VERSION 5.7 ;
BUSBITCHARS "[]" ;
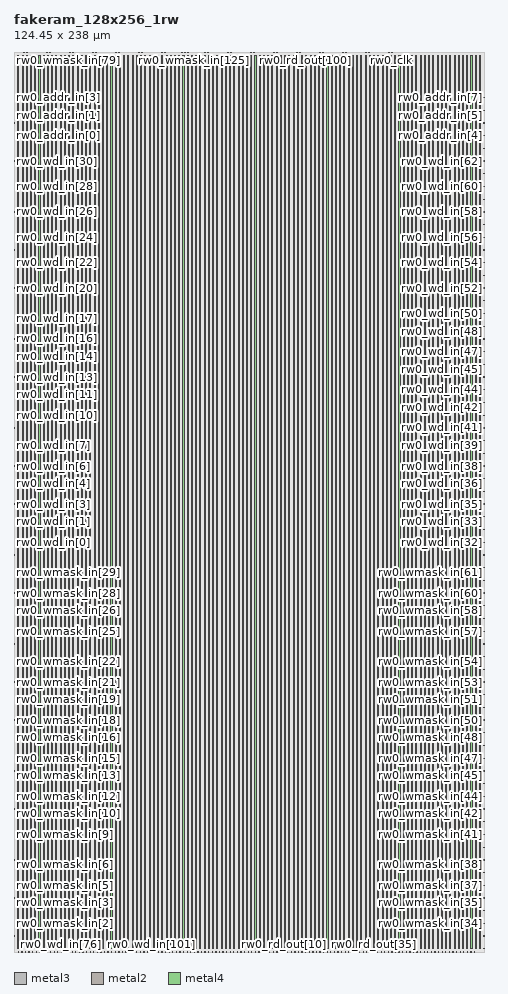
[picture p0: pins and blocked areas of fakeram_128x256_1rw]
MACRO fakeram_128x256_1rw
  FOREIGN fakeram_128x256_1rw 0 0 ;
  SYMMETRY X Y R90 ;
  SIZE 124.450 BY 238.000 ;
  CLASS BLOCK ;
  PIN rw0_wmask_in[0]
    DIRECTION INPUT ;
    USE SIGNAL ;
    SHAPE ABUTMENT ;
    PORT
      LAYER metal3 ;
      RECT 0.000 0.805 0.210 0.875 ;
    END
  END rw0_wmask_in[0]
  PIN rw0_wmask_in[1]
    DIRECTION INPUT ;
    USE SIGNAL ;
    SHAPE ABUTMENT ;
    PORT
      LAYER metal3 ;
      RECT 0.000 4.165 0.210 4.235 ;
    END
  END rw0_wmask_in[1]
  PIN rw0_wmask_in[2]
    DIRECTION INPUT ;
    USE SIGNAL ;
    SHAPE ABUTMENT ;
    PORT
      LAYER metal3 ;
      RECT 0.000 7.525 0.210 7.595 ;
    END
  END rw0_wmask_in[2]
  PIN rw0_wmask_in[3]
    DIRECTION INPUT ;
    USE SIGNAL ;
    SHAPE ABUTMENT ;
    PORT
      LAYER metal3 ;
      RECT 0.000 10.885 0.210 10.955 ;
    END
  END rw0_wmask_in[3]
  PIN rw0_wmask_in[4]
    DIRECTION INPUT ;
    USE SIGNAL ;
    SHAPE ABUTMENT ;
    PORT
      LAYER metal3 ;
      RECT 0.000 14.245 0.210 14.315 ;
    END
  END rw0_wmask_in[4]
  PIN rw0_wmask_in[5]
    DIRECTION INPUT ;
    USE SIGNAL ;
    SHAPE ABUTMENT ;
    PORT
      LAYER metal3 ;
      RECT 0.000 17.605 0.210 17.675 ;
    END
  END rw0_wmask_in[5]
  PIN rw0_wmask_in[6]
    DIRECTION INPUT ;
    USE SIGNAL ;
    SHAPE ABUTMENT ;
    PORT
      LAYER metal3 ;
      RECT 0.000 20.965 0.210 21.035 ;
    END
  END rw0_wmask_in[6]
  PIN rw0_wmask_in[7]
    DIRECTION INPUT ;
    USE SIGNAL ;
    SHAPE ABUTMENT ;
    PORT
      LAYER metal3 ;
      RECT 0.000 24.325 0.210 24.395 ;
    END
  END rw0_wmask_in[7]
  PIN rw0_wmask_in[8]
    DIRECTION INPUT ;
    USE SIGNAL ;
    SHAPE ABUTMENT ;
    PORT
      LAYER metal3 ;
      RECT 0.000 27.685 0.210 27.755 ;
    END
  END rw0_wmask_in[8]
  PIN rw0_wmask_in[9]
    DIRECTION INPUT ;
    USE SIGNAL ;
    SHAPE ABUTMENT ;
    PORT
      LAYER metal3 ;
      RECT 0.000 31.045 0.210 31.115 ;
    END
  END rw0_wmask_in[9]
  PIN rw0_wmask_in[10]
    DIRECTION INPUT ;
    USE SIGNAL ;
    SHAPE ABUTMENT ;
    PORT
      LAYER metal3 ;
      RECT 0.000 34.405 0.210 34.475 ;
    END
  END rw0_wmask_in[10]
  PIN rw0_wmask_in[11]
    DIRECTION INPUT ;
    USE SIGNAL ;
    SHAPE ABUTMENT ;
    PORT
      LAYER metal3 ;
      RECT 0.000 37.765 0.210 37.835 ;
    END
  END rw0_wmask_in[11]
  PIN rw0_wmask_in[12]
    DIRECTION INPUT ;
    USE SIGNAL ;
    SHAPE ABUTMENT ;
    PORT
      LAYER metal3 ;
      RECT 0.000 41.125 0.210 41.195 ;
    END
  END rw0_wmask_in[12]
  PIN rw0_wmask_in[13]
    DIRECTION INPUT ;
    USE SIGNAL ;
    SHAPE ABUTMENT ;
    PORT
      LAYER metal3 ;
      RECT 0.000 44.485 0.210 44.555 ;
    END
  END rw0_wmask_in[13]
  PIN rw0_wmask_in[14]
    DIRECTION INPUT ;
    USE SIGNAL ;
    SHAPE ABUTMENT ;
    PORT
      LAYER metal3 ;
      RECT 0.000 47.845 0.210 47.915 ;
    END
  END rw0_wmask_in[14]
  PIN rw0_wmask_in[15]
    DIRECTION INPUT ;
    USE SIGNAL ;
    SHAPE ABUTMENT ;
    PORT
      LAYER metal3 ;
      RECT 0.000 51.205 0.210 51.275 ;
    END
  END rw0_wmask_in[15]
  PIN rw0_wmask_in[16]
    DIRECTION INPUT ;
    USE SIGNAL ;
    SHAPE ABUTMENT ;
    PORT
      LAYER metal3 ;
      RECT 0.000 54.565 0.210 54.635 ;
    END
  END rw0_wmask_in[16]
  PIN rw0_wmask_in[17]
    DIRECTION INPUT ;
    USE SIGNAL ;
    SHAPE ABUTMENT ;
    PORT
      LAYER metal3 ;
      RECT 0.000 57.925 0.210 57.995 ;
    END
  END rw0_wmask_in[17]
  PIN rw0_wmask_in[18]
    DIRECTION INPUT ;
    USE SIGNAL ;
    SHAPE ABUTMENT ;
    PORT
      LAYER metal3 ;
      RECT 0.000 61.285 0.210 61.355 ;
    END
  END rw0_wmask_in[18]
  PIN rw0_wmask_in[19]
    DIRECTION INPUT ;
    USE SIGNAL ;
    SHAPE ABUTMENT ;
    PORT
      LAYER metal3 ;
      RECT 0.000 64.645 0.210 64.715 ;
    END
  END rw0_wmask_in[19]
  PIN rw0_wmask_in[20]
    DIRECTION INPUT ;
    USE SIGNAL ;
    SHAPE ABUTMENT ;
    PORT
      LAYER metal3 ;
      RECT 0.000 68.005 0.210 68.075 ;
    END
  END rw0_wmask_in[20]
  PIN rw0_wmask_in[21]
    DIRECTION INPUT ;
    USE SIGNAL ;
    SHAPE ABUTMENT ;
    PORT
      LAYER metal3 ;
      RECT 0.000 71.365 0.210 71.435 ;
    END
  END rw0_wmask_in[21]
  PIN rw0_wmask_in[22]
    DIRECTION INPUT ;
    USE SIGNAL ;
    SHAPE ABUTMENT ;
    PORT
      LAYER metal3 ;
      RECT 0.000 74.725 0.210 74.795 ;
    END
  END rw0_wmask_in[22]
  PIN rw0_wmask_in[23]
    DIRECTION INPUT ;
    USE SIGNAL ;
    SHAPE ABUTMENT ;
    PORT
      LAYER metal3 ;
      RECT 0.000 78.085 0.210 78.155 ;
    END
  END rw0_wmask_in[23]
  PIN rw0_wmask_in[24]
    DIRECTION INPUT ;
    USE SIGNAL ;
    SHAPE ABUTMENT ;
    PORT
      LAYER metal3 ;
      RECT 0.000 81.445 0.210 81.515 ;
    END
  END rw0_wmask_in[24]
  PIN rw0_wmask_in[25]
    DIRECTION INPUT ;
    USE SIGNAL ;
    SHAPE ABUTMENT ;
    PORT
      LAYER metal3 ;
      RECT 0.000 84.805 0.210 84.875 ;
    END
  END rw0_wmask_in[25]
  PIN rw0_wmask_in[26]
    DIRECTION INPUT ;
    USE SIGNAL ;
    SHAPE ABUTMENT ;
    PORT
      LAYER metal3 ;
      RECT 0.000 88.165 0.210 88.235 ;
    END
  END rw0_wmask_in[26]
  PIN rw0_wmask_in[27]
    DIRECTION INPUT ;
    USE SIGNAL ;
    SHAPE ABUTMENT ;
    PORT
      LAYER metal3 ;
      RECT 0.000 91.525 0.210 91.595 ;
    END
  END rw0_wmask_in[27]
  PIN rw0_wmask_in[28]
    DIRECTION INPUT ;
    USE SIGNAL ;
    SHAPE ABUTMENT ;
    PORT
      LAYER metal3 ;
      RECT 0.000 94.885 0.210 94.955 ;
    END
  END rw0_wmask_in[28]
  PIN rw0_wmask_in[29]
    DIRECTION INPUT ;
    USE SIGNAL ;
    SHAPE ABUTMENT ;
    PORT
      LAYER metal3 ;
      RECT 0.000 98.245 0.210 98.315 ;
    END
  END rw0_wmask_in[29]
  PIN rw0_wmask_in[30]
    DIRECTION INPUT ;
    USE SIGNAL ;
    SHAPE ABUTMENT ;
    PORT
      LAYER metal3 ;
      RECT 0.000 101.605 0.210 101.675 ;
    END
  END rw0_wmask_in[30]
  PIN rw0_wmask_in[31]
    DIRECTION INPUT ;
    USE SIGNAL ;
    SHAPE ABUTMENT ;
    PORT
      LAYER metal3 ;
      RECT 0.000 104.965 0.210 105.035 ;
    END
  END rw0_wmask_in[31]
  PIN rw0_wmask_in[32]
    DIRECTION INPUT ;
    USE SIGNAL ;
    SHAPE ABUTMENT ;
    PORT
      LAYER metal3 ;
      RECT 124.240 0.805 124.450 0.875 ;
    END
  END rw0_wmask_in[32]
  PIN rw0_wmask_in[33]
    DIRECTION INPUT ;
    USE SIGNAL ;
    SHAPE ABUTMENT ;
    PORT
      LAYER metal3 ;
      RECT 124.240 4.165 124.450 4.235 ;
    END
  END rw0_wmask_in[33]
  PIN rw0_wmask_in[34]
    DIRECTION INPUT ;
    USE SIGNAL ;
    SHAPE ABUTMENT ;
    PORT
      LAYER metal3 ;
      RECT 124.240 7.525 124.450 7.595 ;
    END
  END rw0_wmask_in[34]
  PIN rw0_wmask_in[35]
    DIRECTION INPUT ;
    USE SIGNAL ;
    SHAPE ABUTMENT ;
    PORT
      LAYER metal3 ;
      RECT 124.240 10.885 124.450 10.955 ;
    END
  END rw0_wmask_in[35]
  PIN rw0_wmask_in[36]
    DIRECTION INPUT ;
    USE SIGNAL ;
    SHAPE ABUTMENT ;
    PORT
      LAYER metal3 ;
      RECT 124.240 14.245 124.450 14.315 ;
    END
  END rw0_wmask_in[36]
  PIN rw0_wmask_in[37]
    DIRECTION INPUT ;
    USE SIGNAL ;
    SHAPE ABUTMENT ;
    PORT
      LAYER metal3 ;
      RECT 124.240 17.605 124.450 17.675 ;
    END
  END rw0_wmask_in[37]
  PIN rw0_wmask_in[38]
    DIRECTION INPUT ;
    USE SIGNAL ;
    SHAPE ABUTMENT ;
    PORT
      LAYER metal3 ;
      RECT 124.240 20.965 124.450 21.035 ;
    END
  END rw0_wmask_in[38]
  PIN rw0_wmask_in[39]
    DIRECTION INPUT ;
    USE SIGNAL ;
    SHAPE ABUTMENT ;
    PORT
      LAYER metal3 ;
      RECT 124.240 24.325 124.450 24.395 ;
    END
  END rw0_wmask_in[39]
  PIN rw0_wmask_in[40]
    DIRECTION INPUT ;
    USE SIGNAL ;
    SHAPE ABUTMENT ;
    PORT
      LAYER metal3 ;
      RECT 124.240 27.685 124.450 27.755 ;
    END
  END rw0_wmask_in[40]
  PIN rw0_wmask_in[41]
    DIRECTION INPUT ;
    USE SIGNAL ;
    SHAPE ABUTMENT ;
    PORT
      LAYER metal3 ;
      RECT 124.240 31.045 124.450 31.115 ;
    END
  END rw0_wmask_in[41]
  PIN rw0_wmask_in[42]
    DIRECTION INPUT ;
    USE SIGNAL ;
    SHAPE ABUTMENT ;
    PORT
      LAYER metal3 ;
      RECT 124.240 34.405 124.450 34.475 ;
    END
  END rw0_wmask_in[42]
  PIN rw0_wmask_in[43]
    DIRECTION INPUT ;
    USE SIGNAL ;
    SHAPE ABUTMENT ;
    PORT
      LAYER metal3 ;
      RECT 124.240 37.765 124.450 37.835 ;
    END
  END rw0_wmask_in[43]
  PIN rw0_wmask_in[44]
    DIRECTION INPUT ;
    USE SIGNAL ;
    SHAPE ABUTMENT ;
    PORT
      LAYER metal3 ;
      RECT 124.240 41.125 124.450 41.195 ;
    END
  END rw0_wmask_in[44]
  PIN rw0_wmask_in[45]
    DIRECTION INPUT ;
    USE SIGNAL ;
    SHAPE ABUTMENT ;
    PORT
      LAYER metal3 ;
      RECT 124.240 44.485 124.450 44.555 ;
    END
  END rw0_wmask_in[45]
  PIN rw0_wmask_in[46]
    DIRECTION INPUT ;
    USE SIGNAL ;
    SHAPE ABUTMENT ;
    PORT
      LAYER metal3 ;
      RECT 124.240 47.845 124.450 47.915 ;
    END
  END rw0_wmask_in[46]
  PIN rw0_wmask_in[47]
    DIRECTION INPUT ;
    USE SIGNAL ;
    SHAPE ABUTMENT ;
    PORT
      LAYER metal3 ;
      RECT 124.240 51.205 124.450 51.275 ;
    END
  END rw0_wmask_in[47]
  PIN rw0_wmask_in[48]
    DIRECTION INPUT ;
    USE SIGNAL ;
    SHAPE ABUTMENT ;
    PORT
      LAYER metal3 ;
      RECT 124.240 54.565 124.450 54.635 ;
    END
  END rw0_wmask_in[48]
  PIN rw0_wmask_in[49]
    DIRECTION INPUT ;
    USE SIGNAL ;
    SHAPE ABUTMENT ;
    PORT
      LAYER metal3 ;
      RECT 124.240 57.925 124.450 57.995 ;
    END
  END rw0_wmask_in[49]
  PIN rw0_wmask_in[50]
    DIRECTION INPUT ;
    USE SIGNAL ;
    SHAPE ABUTMENT ;
    PORT
      LAYER metal3 ;
      RECT 124.240 61.285 124.450 61.355 ;
    END
  END rw0_wmask_in[50]
  PIN rw0_wmask_in[51]
    DIRECTION INPUT ;
    USE SIGNAL ;
    SHAPE ABUTMENT ;
    PORT
      LAYER metal3 ;
      RECT 124.240 64.645 124.450 64.715 ;
    END
  END rw0_wmask_in[51]
  PIN rw0_wmask_in[52]
    DIRECTION INPUT ;
    USE SIGNAL ;
    SHAPE ABUTMENT ;
    PORT
      LAYER metal3 ;
      RECT 124.240 68.005 124.450 68.075 ;
    END
  END rw0_wmask_in[52]
  PIN rw0_wmask_in[53]
    DIRECTION INPUT ;
    USE SIGNAL ;
    SHAPE ABUTMENT ;
    PORT
      LAYER metal3 ;
      RECT 124.240 71.365 124.450 71.435 ;
    END
  END rw0_wmask_in[53]
  PIN rw0_wmask_in[54]
    DIRECTION INPUT ;
    USE SIGNAL ;
    SHAPE ABUTMENT ;
    PORT
      LAYER metal3 ;
      RECT 124.240 74.725 124.450 74.795 ;
    END
  END rw0_wmask_in[54]
  PIN rw0_wmask_in[55]
    DIRECTION INPUT ;
    USE SIGNAL ;
    SHAPE ABUTMENT ;
    PORT
      LAYER metal3 ;
      RECT 124.240 78.085 124.450 78.155 ;
    END
  END rw0_wmask_in[55]
  PIN rw0_wmask_in[56]
    DIRECTION INPUT ;
    USE SIGNAL ;
    SHAPE ABUTMENT ;
    PORT
      LAYER metal3 ;
      RECT 124.240 81.445 124.450 81.515 ;
    END
  END rw0_wmask_in[56]
  PIN rw0_wmask_in[57]
    DIRECTION INPUT ;
    USE SIGNAL ;
    SHAPE ABUTMENT ;
    PORT
      LAYER metal3 ;
      RECT 124.240 84.805 124.450 84.875 ;
    END
  END rw0_wmask_in[57]
  PIN rw0_wmask_in[58]
    DIRECTION INPUT ;
    USE SIGNAL ;
    SHAPE ABUTMENT ;
    PORT
      LAYER metal3 ;
      RECT 124.240 88.165 124.450 88.235 ;
    END
  END rw0_wmask_in[58]
  PIN rw0_wmask_in[59]
    DIRECTION INPUT ;
    USE SIGNAL ;
    SHAPE ABUTMENT ;
    PORT
      LAYER metal3 ;
      RECT 124.240 91.525 124.450 91.595 ;
    END
  END rw0_wmask_in[59]
  PIN rw0_wmask_in[60]
    DIRECTION INPUT ;
    USE SIGNAL ;
    SHAPE ABUTMENT ;
    PORT
      LAYER metal3 ;
      RECT 124.240 94.885 124.450 94.955 ;
    END
  END rw0_wmask_in[60]
  PIN rw0_wmask_in[61]
    DIRECTION INPUT ;
    USE SIGNAL ;
    SHAPE ABUTMENT ;
    PORT
      LAYER metal3 ;
      RECT 124.240 98.245 124.450 98.315 ;
    END
  END rw0_wmask_in[61]
  PIN rw0_wmask_in[62]
    DIRECTION INPUT ;
    USE SIGNAL ;
    SHAPE ABUTMENT ;
    PORT
      LAYER metal3 ;
      RECT 124.240 101.605 124.450 101.675 ;
    END
  END rw0_wmask_in[62]
  PIN rw0_wmask_in[63]
    DIRECTION INPUT ;
    USE SIGNAL ;
    SHAPE ABUTMENT ;
    PORT
      LAYER metal3 ;
      RECT 124.240 104.965 124.450 105.035 ;
    END
  END rw0_wmask_in[63]
  PIN rw0_wmask_in[64]
    DIRECTION INPUT ;
    USE SIGNAL ;
    SHAPE ABUTMENT ;
    PORT
      LAYER metal2 ;
      RECT 1.105 237.790 1.175 238.000 ;
    END
  END rw0_wmask_in[64]
  PIN rw0_wmask_in[65]
    DIRECTION INPUT ;
    USE SIGNAL ;
    SHAPE ABUTMENT ;
    PORT
      LAYER metal2 ;
      RECT 1.865 237.790 1.935 238.000 ;
    END
  END rw0_wmask_in[65]
  PIN rw0_wmask_in[66]
    DIRECTION INPUT ;
    USE SIGNAL ;
    SHAPE ABUTMENT ;
    PORT
      LAYER metal2 ;
      RECT 2.625 237.790 2.695 238.000 ;
    END
  END rw0_wmask_in[66]
  PIN rw0_wmask_in[67]
    DIRECTION INPUT ;
    USE SIGNAL ;
    SHAPE ABUTMENT ;
    PORT
      LAYER metal2 ;
      RECT 3.385 237.790 3.455 238.000 ;
    END
  END rw0_wmask_in[67]
  PIN rw0_wmask_in[68]
    DIRECTION INPUT ;
    USE SIGNAL ;
    SHAPE ABUTMENT ;
    PORT
      LAYER metal2 ;
      RECT 4.145 237.790 4.215 238.000 ;
    END
  END rw0_wmask_in[68]
  PIN rw0_wmask_in[69]
    DIRECTION INPUT ;
    USE SIGNAL ;
    SHAPE ABUTMENT ;
    PORT
      LAYER metal2 ;
      RECT 4.905 237.790 4.975 238.000 ;
    END
  END rw0_wmask_in[69]
  PIN rw0_wmask_in[70]
    DIRECTION INPUT ;
    USE SIGNAL ;
    SHAPE ABUTMENT ;
    PORT
      LAYER metal2 ;
      RECT 5.665 237.790 5.735 238.000 ;
    END
  END rw0_wmask_in[70]
  PIN rw0_wmask_in[71]
    DIRECTION INPUT ;
    USE SIGNAL ;
    SHAPE ABUTMENT ;
    PORT
      LAYER metal2 ;
      RECT 6.425 237.790 6.495 238.000 ;
    END
  END rw0_wmask_in[71]
  PIN rw0_wmask_in[72]
    DIRECTION INPUT ;
    USE SIGNAL ;
    SHAPE ABUTMENT ;
    PORT
      LAYER metal2 ;
      RECT 7.185 237.790 7.255 238.000 ;
    END
  END rw0_wmask_in[72]
  PIN rw0_wmask_in[73]
    DIRECTION INPUT ;
    USE SIGNAL ;
    SHAPE ABUTMENT ;
    PORT
      LAYER metal2 ;
      RECT 7.945 237.790 8.015 238.000 ;
    END
  END rw0_wmask_in[73]
  PIN rw0_wmask_in[74]
    DIRECTION INPUT ;
    USE SIGNAL ;
    SHAPE ABUTMENT ;
    PORT
      LAYER metal2 ;
      RECT 8.705 237.790 8.775 238.000 ;
    END
  END rw0_wmask_in[74]
  PIN rw0_wmask_in[75]
    DIRECTION INPUT ;
    USE SIGNAL ;
    SHAPE ABUTMENT ;
    PORT
      LAYER metal2 ;
      RECT 9.465 237.790 9.535 238.000 ;
    END
  END rw0_wmask_in[75]
  PIN rw0_wmask_in[76]
    DIRECTION INPUT ;
    USE SIGNAL ;
    SHAPE ABUTMENT ;
    PORT
      LAYER metal2 ;
      RECT 10.225 237.790 10.295 238.000 ;
    END
  END rw0_wmask_in[76]
  PIN rw0_wmask_in[77]
    DIRECTION INPUT ;
    USE SIGNAL ;
    SHAPE ABUTMENT ;
    PORT
      LAYER metal2 ;
      RECT 10.985 237.790 11.055 238.000 ;
    END
  END rw0_wmask_in[77]
  PIN rw0_wmask_in[78]
    DIRECTION INPUT ;
    USE SIGNAL ;
    SHAPE ABUTMENT ;
    PORT
      LAYER metal2 ;
      RECT 11.745 237.790 11.815 238.000 ;
    END
  END rw0_wmask_in[78]
  PIN rw0_wmask_in[79]
    DIRECTION INPUT ;
    USE SIGNAL ;
    SHAPE ABUTMENT ;
    PORT
      LAYER metal2 ;
      RECT 12.505 237.790 12.575 238.000 ;
    END
  END rw0_wmask_in[79]
  PIN rw0_wmask_in[80]
    DIRECTION INPUT ;
    USE SIGNAL ;
    SHAPE ABUTMENT ;
    PORT
      LAYER metal2 ;
      RECT 13.265 237.790 13.335 238.000 ;
    END
  END rw0_wmask_in[80]
  PIN rw0_wmask_in[81]
    DIRECTION INPUT ;
    USE SIGNAL ;
    SHAPE ABUTMENT ;
    PORT
      LAYER metal2 ;
      RECT 14.025 237.790 14.095 238.000 ;
    END
  END rw0_wmask_in[81]
  PIN rw0_wmask_in[82]
    DIRECTION INPUT ;
    USE SIGNAL ;
    SHAPE ABUTMENT ;
    PORT
      LAYER metal2 ;
      RECT 14.785 237.790 14.855 238.000 ;
    END
  END rw0_wmask_in[82]
  PIN rw0_wmask_in[83]
    DIRECTION INPUT ;
    USE SIGNAL ;
    SHAPE ABUTMENT ;
    PORT
      LAYER metal2 ;
      RECT 15.545 237.790 15.615 238.000 ;
    END
  END rw0_wmask_in[83]
  PIN rw0_wmask_in[84]
    DIRECTION INPUT ;
    USE SIGNAL ;
    SHAPE ABUTMENT ;
    PORT
      LAYER metal2 ;
      RECT 16.305 237.790 16.375 238.000 ;
    END
  END rw0_wmask_in[84]
  PIN rw0_wmask_in[85]
    DIRECTION INPUT ;
    USE SIGNAL ;
    SHAPE ABUTMENT ;
    PORT
      LAYER metal2 ;
      RECT 17.065 237.790 17.135 238.000 ;
    END
  END rw0_wmask_in[85]
  PIN rw0_wmask_in[86]
    DIRECTION INPUT ;
    USE SIGNAL ;
    SHAPE ABUTMENT ;
    PORT
      LAYER metal2 ;
      RECT 17.825 237.790 17.895 238.000 ;
    END
  END rw0_wmask_in[86]
  PIN rw0_wmask_in[87]
    DIRECTION INPUT ;
    USE SIGNAL ;
    SHAPE ABUTMENT ;
    PORT
      LAYER metal2 ;
      RECT 18.585 237.790 18.655 238.000 ;
    END
  END rw0_wmask_in[87]
  PIN rw0_wmask_in[88]
    DIRECTION INPUT ;
    USE SIGNAL ;
    SHAPE ABUTMENT ;
    PORT
      LAYER metal2 ;
      RECT 19.345 237.790 19.415 238.000 ;
    END
  END rw0_wmask_in[88]
  PIN rw0_wmask_in[89]
    DIRECTION INPUT ;
    USE SIGNAL ;
    SHAPE ABUTMENT ;
    PORT
      LAYER metal2 ;
      RECT 20.105 237.790 20.175 238.000 ;
    END
  END rw0_wmask_in[89]
  PIN rw0_wmask_in[90]
    DIRECTION INPUT ;
    USE SIGNAL ;
    SHAPE ABUTMENT ;
    PORT
      LAYER metal2 ;
      RECT 20.865 237.790 20.935 238.000 ;
    END
  END rw0_wmask_in[90]
  PIN rw0_wmask_in[91]
    DIRECTION INPUT ;
    USE SIGNAL ;
    SHAPE ABUTMENT ;
    PORT
      LAYER metal2 ;
      RECT 21.625 237.790 21.695 238.000 ;
    END
  END rw0_wmask_in[91]
  PIN rw0_wmask_in[92]
    DIRECTION INPUT ;
    USE SIGNAL ;
    SHAPE ABUTMENT ;
    PORT
      LAYER metal2 ;
      RECT 22.385 237.790 22.455 238.000 ;
    END
  END rw0_wmask_in[92]
  PIN rw0_wmask_in[93]
    DIRECTION INPUT ;
    USE SIGNAL ;
    SHAPE ABUTMENT ;
    PORT
      LAYER metal2 ;
      RECT 23.145 237.790 23.215 238.000 ;
    END
  END rw0_wmask_in[93]
  PIN rw0_wmask_in[94]
    DIRECTION INPUT ;
    USE SIGNAL ;
    SHAPE ABUTMENT ;
    PORT
      LAYER metal2 ;
      RECT 23.905 237.790 23.975 238.000 ;
    END
  END rw0_wmask_in[94]
  PIN rw0_wmask_in[95]
    DIRECTION INPUT ;
    USE SIGNAL ;
    SHAPE ABUTMENT ;
    PORT
      LAYER metal2 ;
      RECT 24.665 237.790 24.735 238.000 ;
    END
  END rw0_wmask_in[95]
  PIN rw0_wmask_in[96]
    DIRECTION INPUT ;
    USE SIGNAL ;
    SHAPE ABUTMENT ;
    PORT
      LAYER metal2 ;
      RECT 25.425 237.790 25.495 238.000 ;
    END
  END rw0_wmask_in[96]
  PIN rw0_wmask_in[97]
    DIRECTION INPUT ;
    USE SIGNAL ;
    SHAPE ABUTMENT ;
    PORT
      LAYER metal2 ;
      RECT 26.185 237.790 26.255 238.000 ;
    END
  END rw0_wmask_in[97]
  PIN rw0_wmask_in[98]
    DIRECTION INPUT ;
    USE SIGNAL ;
    SHAPE ABUTMENT ;
    PORT
      LAYER metal2 ;
      RECT 26.945 237.790 27.015 238.000 ;
    END
  END rw0_wmask_in[98]
  PIN rw0_wmask_in[99]
    DIRECTION INPUT ;
    USE SIGNAL ;
    SHAPE ABUTMENT ;
    PORT
      LAYER metal2 ;
      RECT 27.705 237.790 27.775 238.000 ;
    END
  END rw0_wmask_in[99]
  PIN rw0_wmask_in[100]
    DIRECTION INPUT ;
    USE SIGNAL ;
    SHAPE ABUTMENT ;
    PORT
      LAYER metal2 ;
      RECT 28.465 237.790 28.535 238.000 ;
    END
  END rw0_wmask_in[100]
  PIN rw0_wmask_in[101]
    DIRECTION INPUT ;
    USE SIGNAL ;
    SHAPE ABUTMENT ;
    PORT
      LAYER metal2 ;
      RECT 29.225 237.790 29.295 238.000 ;
    END
  END rw0_wmask_in[101]
  PIN rw0_wmask_in[102]
    DIRECTION INPUT ;
    USE SIGNAL ;
    SHAPE ABUTMENT ;
    PORT
      LAYER metal2 ;
      RECT 29.985 237.790 30.055 238.000 ;
    END
  END rw0_wmask_in[102]
  PIN rw0_wmask_in[103]
    DIRECTION INPUT ;
    USE SIGNAL ;
    SHAPE ABUTMENT ;
    PORT
      LAYER metal2 ;
      RECT 30.745 237.790 30.815 238.000 ;
    END
  END rw0_wmask_in[103]
  PIN rw0_wmask_in[104]
    DIRECTION INPUT ;
    USE SIGNAL ;
    SHAPE ABUTMENT ;
    PORT
      LAYER metal2 ;
      RECT 31.505 237.790 31.575 238.000 ;
    END
  END rw0_wmask_in[104]
  PIN rw0_wmask_in[105]
    DIRECTION INPUT ;
    USE SIGNAL ;
    SHAPE ABUTMENT ;
    PORT
      LAYER metal2 ;
      RECT 32.265 237.790 32.335 238.000 ;
    END
  END rw0_wmask_in[105]
  PIN rw0_wmask_in[106]
    DIRECTION INPUT ;
    USE SIGNAL ;
    SHAPE ABUTMENT ;
    PORT
      LAYER metal2 ;
      RECT 33.025 237.790 33.095 238.000 ;
    END
  END rw0_wmask_in[106]
  PIN rw0_wmask_in[107]
    DIRECTION INPUT ;
    USE SIGNAL ;
    SHAPE ABUTMENT ;
    PORT
      LAYER metal2 ;
      RECT 33.785 237.790 33.855 238.000 ;
    END
  END rw0_wmask_in[107]
  PIN rw0_wmask_in[108]
    DIRECTION INPUT ;
    USE SIGNAL ;
    SHAPE ABUTMENT ;
    PORT
      LAYER metal2 ;
      RECT 34.545 237.790 34.615 238.000 ;
    END
  END rw0_wmask_in[108]
  PIN rw0_wmask_in[109]
    DIRECTION INPUT ;
    USE SIGNAL ;
    SHAPE ABUTMENT ;
    PORT
      LAYER metal2 ;
      RECT 35.305 237.790 35.375 238.000 ;
    END
  END rw0_wmask_in[109]
  PIN rw0_wmask_in[110]
    DIRECTION INPUT ;
    USE SIGNAL ;
    SHAPE ABUTMENT ;
    PORT
      LAYER metal2 ;
      RECT 36.065 237.790 36.135 238.000 ;
    END
  END rw0_wmask_in[110]
  PIN rw0_wmask_in[111]
    DIRECTION INPUT ;
    USE SIGNAL ;
    SHAPE ABUTMENT ;
    PORT
      LAYER metal2 ;
      RECT 36.825 237.790 36.895 238.000 ;
    END
  END rw0_wmask_in[111]
  PIN rw0_wmask_in[112]
    DIRECTION INPUT ;
    USE SIGNAL ;
    SHAPE ABUTMENT ;
    PORT
      LAYER metal2 ;
      RECT 37.585 237.790 37.655 238.000 ;
    END
  END rw0_wmask_in[112]
  PIN rw0_wmask_in[113]
    DIRECTION INPUT ;
    USE SIGNAL ;
    SHAPE ABUTMENT ;
    PORT
      LAYER metal2 ;
      RECT 38.345 237.790 38.415 238.000 ;
    END
  END rw0_wmask_in[113]
  PIN rw0_wmask_in[114]
    DIRECTION INPUT ;
    USE SIGNAL ;
    SHAPE ABUTMENT ;
    PORT
      LAYER metal2 ;
      RECT 39.105 237.790 39.175 238.000 ;
    END
  END rw0_wmask_in[114]
  PIN rw0_wmask_in[115]
    DIRECTION INPUT ;
    USE SIGNAL ;
    SHAPE ABUTMENT ;
    PORT
      LAYER metal2 ;
      RECT 39.865 237.790 39.935 238.000 ;
    END
  END rw0_wmask_in[115]
  PIN rw0_wmask_in[116]
    DIRECTION INPUT ;
    USE SIGNAL ;
    SHAPE ABUTMENT ;
    PORT
      LAYER metal2 ;
      RECT 40.625 237.790 40.695 238.000 ;
    END
  END rw0_wmask_in[116]
  PIN rw0_wmask_in[117]
    DIRECTION INPUT ;
    USE SIGNAL ;
    SHAPE ABUTMENT ;
    PORT
      LAYER metal2 ;
      RECT 41.385 237.790 41.455 238.000 ;
    END
  END rw0_wmask_in[117]
  PIN rw0_wmask_in[118]
    DIRECTION INPUT ;
    USE SIGNAL ;
    SHAPE ABUTMENT ;
    PORT
      LAYER metal2 ;
      RECT 42.145 237.790 42.215 238.000 ;
    END
  END rw0_wmask_in[118]
  PIN rw0_wmask_in[119]
    DIRECTION INPUT ;
    USE SIGNAL ;
    SHAPE ABUTMENT ;
    PORT
      LAYER metal2 ;
      RECT 42.905 237.790 42.975 238.000 ;
    END
  END rw0_wmask_in[119]
  PIN rw0_wmask_in[120]
    DIRECTION INPUT ;
    USE SIGNAL ;
    SHAPE ABUTMENT ;
    PORT
      LAYER metal2 ;
      RECT 43.665 237.790 43.735 238.000 ;
    END
  END rw0_wmask_in[120]
  PIN rw0_wmask_in[121]
    DIRECTION INPUT ;
    USE SIGNAL ;
    SHAPE ABUTMENT ;
    PORT
      LAYER metal2 ;
      RECT 44.425 237.790 44.495 238.000 ;
    END
  END rw0_wmask_in[121]
  PIN rw0_wmask_in[122]
    DIRECTION INPUT ;
    USE SIGNAL ;
    SHAPE ABUTMENT ;
    PORT
      LAYER metal2 ;
      RECT 45.185 237.790 45.255 238.000 ;
    END
  END rw0_wmask_in[122]
  PIN rw0_wmask_in[123]
    DIRECTION INPUT ;
    USE SIGNAL ;
    SHAPE ABUTMENT ;
    PORT
      LAYER metal2 ;
      RECT 45.945 237.790 46.015 238.000 ;
    END
  END rw0_wmask_in[123]
  PIN rw0_wmask_in[124]
    DIRECTION INPUT ;
    USE SIGNAL ;
    SHAPE ABUTMENT ;
    PORT
      LAYER metal2 ;
      RECT 46.705 237.790 46.775 238.000 ;
    END
  END rw0_wmask_in[124]
  PIN rw0_wmask_in[125]
    DIRECTION INPUT ;
    USE SIGNAL ;
    SHAPE ABUTMENT ;
    PORT
      LAYER metal2 ;
      RECT 47.465 237.790 47.535 238.000 ;
    END
  END rw0_wmask_in[125]
  PIN rw0_wmask_in[126]
    DIRECTION INPUT ;
    USE SIGNAL ;
    SHAPE ABUTMENT ;
    PORT
      LAYER metal2 ;
      RECT 48.225 237.790 48.295 238.000 ;
    END
  END rw0_wmask_in[126]
  PIN rw0_wmask_in[127]
    DIRECTION INPUT ;
    USE SIGNAL ;
    SHAPE ABUTMENT ;
    PORT
      LAYER metal2 ;
      RECT 48.985 237.790 49.055 238.000 ;
    END
  END rw0_wmask_in[127]
  PIN rw0_wd_in[0]
    DIRECTION INPUT ;
    USE SIGNAL ;
    SHAPE ABUTMENT ;
    PORT
      LAYER metal3 ;
      RECT 0.000 108.325 0.210 108.395 ;
    END
  END rw0_wd_in[0]
  PIN rw0_wd_in[1]
    DIRECTION INPUT ;
    USE SIGNAL ;
    SHAPE ABUTMENT ;
    PORT
      LAYER metal3 ;
      RECT 0.000 111.685 0.210 111.755 ;
    END
  END rw0_wd_in[1]
  PIN rw0_wd_in[2]
    DIRECTION INPUT ;
    USE SIGNAL ;
    SHAPE ABUTMENT ;
    PORT
      LAYER metal3 ;
      RECT 0.000 115.045 0.210 115.115 ;
    END
  END rw0_wd_in[2]
  PIN rw0_wd_in[3]
    DIRECTION INPUT ;
    USE SIGNAL ;
    SHAPE ABUTMENT ;
    PORT
      LAYER metal3 ;
      RECT 0.000 118.405 0.210 118.475 ;
    END
  END rw0_wd_in[3]
  PIN rw0_wd_in[4]
    DIRECTION INPUT ;
    USE SIGNAL ;
    SHAPE ABUTMENT ;
    PORT
      LAYER metal3 ;
      RECT 0.000 121.765 0.210 121.835 ;
    END
  END rw0_wd_in[4]
  PIN rw0_wd_in[5]
    DIRECTION INPUT ;
    USE SIGNAL ;
    SHAPE ABUTMENT ;
    PORT
      LAYER metal3 ;
      RECT 0.000 125.125 0.210 125.195 ;
    END
  END rw0_wd_in[5]
  PIN rw0_wd_in[6]
    DIRECTION INPUT ;
    USE SIGNAL ;
    SHAPE ABUTMENT ;
    PORT
      LAYER metal3 ;
      RECT 0.000 128.485 0.210 128.555 ;
    END
  END rw0_wd_in[6]
  PIN rw0_wd_in[7]
    DIRECTION INPUT ;
    USE SIGNAL ;
    SHAPE ABUTMENT ;
    PORT
      LAYER metal3 ;
      RECT 0.000 131.845 0.210 131.915 ;
    END
  END rw0_wd_in[7]
  PIN rw0_wd_in[8]
    DIRECTION INPUT ;
    USE SIGNAL ;
    SHAPE ABUTMENT ;
    PORT
      LAYER metal3 ;
      RECT 0.000 135.205 0.210 135.275 ;
    END
  END rw0_wd_in[8]
  PIN rw0_wd_in[9]
    DIRECTION INPUT ;
    USE SIGNAL ;
    SHAPE ABUTMENT ;
    PORT
      LAYER metal3 ;
      RECT 0.000 138.565 0.210 138.635 ;
    END
  END rw0_wd_in[9]
  PIN rw0_wd_in[10]
    DIRECTION INPUT ;
    USE SIGNAL ;
    SHAPE ABUTMENT ;
    PORT
      LAYER metal3 ;
      RECT 0.000 141.925 0.210 141.995 ;
    END
  END rw0_wd_in[10]
  PIN rw0_wd_in[11]
    DIRECTION INPUT ;
    USE SIGNAL ;
    SHAPE ABUTMENT ;
    PORT
      LAYER metal3 ;
      RECT 0.000 145.285 0.210 145.355 ;
    END
  END rw0_wd_in[11]
  PIN rw0_wd_in[12]
    DIRECTION INPUT ;
    USE SIGNAL ;
    SHAPE ABUTMENT ;
    PORT
      LAYER metal3 ;
      RECT 0.000 148.645 0.210 148.715 ;
    END
  END rw0_wd_in[12]
  PIN rw0_wd_in[13]
    DIRECTION INPUT ;
    USE SIGNAL ;
    SHAPE ABUTMENT ;
    PORT
      LAYER metal3 ;
      RECT 0.000 152.005 0.210 152.075 ;
    END
  END rw0_wd_in[13]
  PIN rw0_wd_in[14]
    DIRECTION INPUT ;
    USE SIGNAL ;
    SHAPE ABUTMENT ;
    PORT
      LAYER metal3 ;
      RECT 0.000 155.365 0.210 155.435 ;
    END
  END rw0_wd_in[14]
  PIN rw0_wd_in[15]
    DIRECTION INPUT ;
    USE SIGNAL ;
    SHAPE ABUTMENT ;
    PORT
      LAYER metal3 ;
      RECT 0.000 158.725 0.210 158.795 ;
    END
  END rw0_wd_in[15]
  PIN rw0_wd_in[16]
    DIRECTION INPUT ;
    USE SIGNAL ;
    SHAPE ABUTMENT ;
    PORT
      LAYER metal3 ;
      RECT 0.000 162.085 0.210 162.155 ;
    END
  END rw0_wd_in[16]
  PIN rw0_wd_in[17]
    DIRECTION INPUT ;
    USE SIGNAL ;
    SHAPE ABUTMENT ;
    PORT
      LAYER metal3 ;
      RECT 0.000 165.445 0.210 165.515 ;
    END
  END rw0_wd_in[17]
  PIN rw0_wd_in[18]
    DIRECTION INPUT ;
    USE SIGNAL ;
    SHAPE ABUTMENT ;
    PORT
      LAYER metal3 ;
      RECT 0.000 168.805 0.210 168.875 ;
    END
  END rw0_wd_in[18]
  PIN rw0_wd_in[19]
    DIRECTION INPUT ;
    USE SIGNAL ;
    SHAPE ABUTMENT ;
    PORT
      LAYER metal3 ;
      RECT 0.000 172.165 0.210 172.235 ;
    END
  END rw0_wd_in[19]
  PIN rw0_wd_in[20]
    DIRECTION INPUT ;
    USE SIGNAL ;
    SHAPE ABUTMENT ;
    PORT
      LAYER metal3 ;
      RECT 0.000 175.525 0.210 175.595 ;
    END
  END rw0_wd_in[20]
  PIN rw0_wd_in[21]
    DIRECTION INPUT ;
    USE SIGNAL ;
    SHAPE ABUTMENT ;
    PORT
      LAYER metal3 ;
      RECT 0.000 178.885 0.210 178.955 ;
    END
  END rw0_wd_in[21]
  PIN rw0_wd_in[22]
    DIRECTION INPUT ;
    USE SIGNAL ;
    SHAPE ABUTMENT ;
    PORT
      LAYER metal3 ;
      RECT 0.000 182.245 0.210 182.315 ;
    END
  END rw0_wd_in[22]
  PIN rw0_wd_in[23]
    DIRECTION INPUT ;
    USE SIGNAL ;
    SHAPE ABUTMENT ;
    PORT
      LAYER metal3 ;
      RECT 0.000 185.605 0.210 185.675 ;
    END
  END rw0_wd_in[23]
  PIN rw0_wd_in[24]
    DIRECTION INPUT ;
    USE SIGNAL ;
    SHAPE ABUTMENT ;
    PORT
      LAYER metal3 ;
      RECT 0.000 188.965 0.210 189.035 ;
    END
  END rw0_wd_in[24]
  PIN rw0_wd_in[25]
    DIRECTION INPUT ;
    USE SIGNAL ;
    SHAPE ABUTMENT ;
    PORT
      LAYER metal3 ;
      RECT 0.000 192.325 0.210 192.395 ;
    END
  END rw0_wd_in[25]
  PIN rw0_wd_in[26]
    DIRECTION INPUT ;
    USE SIGNAL ;
    SHAPE ABUTMENT ;
    PORT
      LAYER metal3 ;
      RECT 0.000 195.685 0.210 195.755 ;
    END
  END rw0_wd_in[26]
  PIN rw0_wd_in[27]
    DIRECTION INPUT ;
    USE SIGNAL ;
    SHAPE ABUTMENT ;
    PORT
      LAYER metal3 ;
      RECT 0.000 199.045 0.210 199.115 ;
    END
  END rw0_wd_in[27]
  PIN rw0_wd_in[28]
    DIRECTION INPUT ;
    USE SIGNAL ;
    SHAPE ABUTMENT ;
    PORT
      LAYER metal3 ;
      RECT 0.000 202.405 0.210 202.475 ;
    END
  END rw0_wd_in[28]
  PIN rw0_wd_in[29]
    DIRECTION INPUT ;
    USE SIGNAL ;
    SHAPE ABUTMENT ;
    PORT
      LAYER metal3 ;
      RECT 0.000 205.765 0.210 205.835 ;
    END
  END rw0_wd_in[29]
  PIN rw0_wd_in[30]
    DIRECTION INPUT ;
    USE SIGNAL ;
    SHAPE ABUTMENT ;
    PORT
      LAYER metal3 ;
      RECT 0.000 209.125 0.210 209.195 ;
    END
  END rw0_wd_in[30]
  PIN rw0_wd_in[31]
    DIRECTION INPUT ;
    USE SIGNAL ;
    SHAPE ABUTMENT ;
    PORT
      LAYER metal3 ;
      RECT 0.000 212.485 0.210 212.555 ;
    END
  END rw0_wd_in[31]
  PIN rw0_wd_in[32]
    DIRECTION INPUT ;
    USE SIGNAL ;
    SHAPE ABUTMENT ;
    PORT
      LAYER metal3 ;
      RECT 124.240 108.325 124.450 108.395 ;
    END
  END rw0_wd_in[32]
  PIN rw0_wd_in[33]
    DIRECTION INPUT ;
    USE SIGNAL ;
    SHAPE ABUTMENT ;
    PORT
      LAYER metal3 ;
      RECT 124.240 111.685 124.450 111.755 ;
    END
  END rw0_wd_in[33]
  PIN rw0_wd_in[34]
    DIRECTION INPUT ;
    USE SIGNAL ;
    SHAPE ABUTMENT ;
    PORT
      LAYER metal3 ;
      RECT 124.240 115.045 124.450 115.115 ;
    END
  END rw0_wd_in[34]
  PIN rw0_wd_in[35]
    DIRECTION INPUT ;
    USE SIGNAL ;
    SHAPE ABUTMENT ;
    PORT
      LAYER metal3 ;
      RECT 124.240 118.405 124.450 118.475 ;
    END
  END rw0_wd_in[35]
  PIN rw0_wd_in[36]
    DIRECTION INPUT ;
    USE SIGNAL ;
    SHAPE ABUTMENT ;
    PORT
      LAYER metal3 ;
      RECT 124.240 121.765 124.450 121.835 ;
    END
  END rw0_wd_in[36]
  PIN rw0_wd_in[37]
    DIRECTION INPUT ;
    USE SIGNAL ;
    SHAPE ABUTMENT ;
    PORT
      LAYER metal3 ;
      RECT 124.240 125.125 124.450 125.195 ;
    END
  END rw0_wd_in[37]
  PIN rw0_wd_in[38]
    DIRECTION INPUT ;
    USE SIGNAL ;
    SHAPE ABUTMENT ;
    PORT
      LAYER metal3 ;
      RECT 124.240 128.485 124.450 128.555 ;
    END
  END rw0_wd_in[38]
  PIN rw0_wd_in[39]
    DIRECTION INPUT ;
    USE SIGNAL ;
    SHAPE ABUTMENT ;
    PORT
      LAYER metal3 ;
      RECT 124.240 131.845 124.450 131.915 ;
    END
  END rw0_wd_in[39]
  PIN rw0_wd_in[40]
    DIRECTION INPUT ;
    USE SIGNAL ;
    SHAPE ABUTMENT ;
    PORT
      LAYER metal3 ;
      RECT 124.240 135.205 124.450 135.275 ;
    END
  END rw0_wd_in[40]
  PIN rw0_wd_in[41]
    DIRECTION INPUT ;
    USE SIGNAL ;
    SHAPE ABUTMENT ;
    PORT
      LAYER metal3 ;
      RECT 124.240 138.565 124.450 138.635 ;
    END
  END rw0_wd_in[41]
  PIN rw0_wd_in[42]
    DIRECTION INPUT ;
    USE SIGNAL ;
    SHAPE ABUTMENT ;
    PORT
      LAYER metal3 ;
      RECT 124.240 141.925 124.450 141.995 ;
    END
  END rw0_wd_in[42]
  PIN rw0_wd_in[43]
    DIRECTION INPUT ;
    USE SIGNAL ;
    SHAPE ABUTMENT ;
    PORT
      LAYER metal3 ;
      RECT 124.240 145.285 124.450 145.355 ;
    END
  END rw0_wd_in[43]
  PIN rw0_wd_in[44]
    DIRECTION INPUT ;
    USE SIGNAL ;
    SHAPE ABUTMENT ;
    PORT
      LAYER metal3 ;
      RECT 124.240 148.645 124.450 148.715 ;
    END
  END rw0_wd_in[44]
  PIN rw0_wd_in[45]
    DIRECTION INPUT ;
    USE SIGNAL ;
    SHAPE ABUTMENT ;
    PORT
      LAYER metal3 ;
      RECT 124.240 152.005 124.450 152.075 ;
    END
  END rw0_wd_in[45]
  PIN rw0_wd_in[46]
    DIRECTION INPUT ;
    USE SIGNAL ;
    SHAPE ABUTMENT ;
    PORT
      LAYER metal3 ;
      RECT 124.240 155.365 124.450 155.435 ;
    END
  END rw0_wd_in[46]
  PIN rw0_wd_in[47]
    DIRECTION INPUT ;
    USE SIGNAL ;
    SHAPE ABUTMENT ;
    PORT
      LAYER metal3 ;
      RECT 124.240 158.725 124.450 158.795 ;
    END
  END rw0_wd_in[47]
  PIN rw0_wd_in[48]
    DIRECTION INPUT ;
    USE SIGNAL ;
    SHAPE ABUTMENT ;
    PORT
      LAYER metal3 ;
      RECT 124.240 162.085 124.450 162.155 ;
    END
  END rw0_wd_in[48]
  PIN rw0_wd_in[49]
    DIRECTION INPUT ;
    USE SIGNAL ;
    SHAPE ABUTMENT ;
    PORT
      LAYER metal3 ;
      RECT 124.240 165.445 124.450 165.515 ;
    END
  END rw0_wd_in[49]
  PIN rw0_wd_in[50]
    DIRECTION INPUT ;
    USE SIGNAL ;
    SHAPE ABUTMENT ;
    PORT
      LAYER metal3 ;
      RECT 124.240 168.805 124.450 168.875 ;
    END
  END rw0_wd_in[50]
  PIN rw0_wd_in[51]
    DIRECTION INPUT ;
    USE SIGNAL ;
    SHAPE ABUTMENT ;
    PORT
      LAYER metal3 ;
      RECT 124.240 172.165 124.450 172.235 ;
    END
  END rw0_wd_in[51]
  PIN rw0_wd_in[52]
    DIRECTION INPUT ;
    USE SIGNAL ;
    SHAPE ABUTMENT ;
    PORT
      LAYER metal3 ;
      RECT 124.240 175.525 124.450 175.595 ;
    END
  END rw0_wd_in[52]
  PIN rw0_wd_in[53]
    DIRECTION INPUT ;
    USE SIGNAL ;
    SHAPE ABUTMENT ;
    PORT
      LAYER metal3 ;
      RECT 124.240 178.885 124.450 178.955 ;
    END
  END rw0_wd_in[53]
  PIN rw0_wd_in[54]
    DIRECTION INPUT ;
    USE SIGNAL ;
    SHAPE ABUTMENT ;
    PORT
      LAYER metal3 ;
      RECT 124.240 182.245 124.450 182.315 ;
    END
  END rw0_wd_in[54]
  PIN rw0_wd_in[55]
    DIRECTION INPUT ;
    USE SIGNAL ;
    SHAPE ABUTMENT ;
    PORT
      LAYER metal3 ;
      RECT 124.240 185.605 124.450 185.675 ;
    END
  END rw0_wd_in[55]
  PIN rw0_wd_in[56]
    DIRECTION INPUT ;
    USE SIGNAL ;
    SHAPE ABUTMENT ;
    PORT
      LAYER metal3 ;
      RECT 124.240 188.965 124.450 189.035 ;
    END
  END rw0_wd_in[56]
  PIN rw0_wd_in[57]
    DIRECTION INPUT ;
    USE SIGNAL ;
    SHAPE ABUTMENT ;
    PORT
      LAYER metal3 ;
      RECT 124.240 192.325 124.450 192.395 ;
    END
  END rw0_wd_in[57]
  PIN rw0_wd_in[58]
    DIRECTION INPUT ;
    USE SIGNAL ;
    SHAPE ABUTMENT ;
    PORT
      LAYER metal3 ;
      RECT 124.240 195.685 124.450 195.755 ;
    END
  END rw0_wd_in[58]
  PIN rw0_wd_in[59]
    DIRECTION INPUT ;
    USE SIGNAL ;
    SHAPE ABUTMENT ;
    PORT
      LAYER metal3 ;
      RECT 124.240 199.045 124.450 199.115 ;
    END
  END rw0_wd_in[59]
  PIN rw0_wd_in[60]
    DIRECTION INPUT ;
    USE SIGNAL ;
    SHAPE ABUTMENT ;
    PORT
      LAYER metal3 ;
      RECT 124.240 202.405 124.450 202.475 ;
    END
  END rw0_wd_in[60]
  PIN rw0_wd_in[61]
    DIRECTION INPUT ;
    USE SIGNAL ;
    SHAPE ABUTMENT ;
    PORT
      LAYER metal3 ;
      RECT 124.240 205.765 124.450 205.835 ;
    END
  END rw0_wd_in[61]
  PIN rw0_wd_in[62]
    DIRECTION INPUT ;
    USE SIGNAL ;
    SHAPE ABUTMENT ;
    PORT
      LAYER metal3 ;
      RECT 124.240 209.125 124.450 209.195 ;
    END
  END rw0_wd_in[62]
  PIN rw0_wd_in[63]
    DIRECTION INPUT ;
    USE SIGNAL ;
    SHAPE ABUTMENT ;
    PORT
      LAYER metal3 ;
      RECT 124.240 212.485 124.450 212.555 ;
    END
  END rw0_wd_in[63]
  PIN rw0_wd_in[64]
    DIRECTION INPUT ;
    USE SIGNAL ;
    SHAPE ABUTMENT ;
    PORT
      LAYER metal2 ;
      RECT 1.105 0.000 1.175 0.210 ;
    END
  END rw0_wd_in[64]
  PIN rw0_wd_in[65]
    DIRECTION INPUT ;
    USE SIGNAL ;
    SHAPE ABUTMENT ;
    PORT
      LAYER metal2 ;
      RECT 2.055 0.000 2.125 0.210 ;
    END
  END rw0_wd_in[65]
  PIN rw0_wd_in[66]
    DIRECTION INPUT ;
    USE SIGNAL ;
    SHAPE ABUTMENT ;
    PORT
      LAYER metal2 ;
      RECT 3.005 0.000 3.075 0.210 ;
    END
  END rw0_wd_in[66]
  PIN rw0_wd_in[67]
    DIRECTION INPUT ;
    USE SIGNAL ;
    SHAPE ABUTMENT ;
    PORT
      LAYER metal2 ;
      RECT 3.955 0.000 4.025 0.210 ;
    END
  END rw0_wd_in[67]
  PIN rw0_wd_in[68]
    DIRECTION INPUT ;
    USE SIGNAL ;
    SHAPE ABUTMENT ;
    PORT
      LAYER metal2 ;
      RECT 4.905 0.000 4.975 0.210 ;
    END
  END rw0_wd_in[68]
  PIN rw0_wd_in[69]
    DIRECTION INPUT ;
    USE SIGNAL ;
    SHAPE ABUTMENT ;
    PORT
      LAYER metal2 ;
      RECT 5.855 0.000 5.925 0.210 ;
    END
  END rw0_wd_in[69]
  PIN rw0_wd_in[70]
    DIRECTION INPUT ;
    USE SIGNAL ;
    SHAPE ABUTMENT ;
    PORT
      LAYER metal2 ;
      RECT 6.805 0.000 6.875 0.210 ;
    END
  END rw0_wd_in[70]
  PIN rw0_wd_in[71]
    DIRECTION INPUT ;
    USE SIGNAL ;
    SHAPE ABUTMENT ;
    PORT
      LAYER metal2 ;
      RECT 7.755 0.000 7.825 0.210 ;
    END
  END rw0_wd_in[71]
  PIN rw0_wd_in[72]
    DIRECTION INPUT ;
    USE SIGNAL ;
    SHAPE ABUTMENT ;
    PORT
      LAYER metal2 ;
      RECT 8.705 0.000 8.775 0.210 ;
    END
  END rw0_wd_in[72]
  PIN rw0_wd_in[73]
    DIRECTION INPUT ;
    USE SIGNAL ;
    SHAPE ABUTMENT ;
    PORT
      LAYER metal2 ;
      RECT 9.655 0.000 9.725 0.210 ;
    END
  END rw0_wd_in[73]
  PIN rw0_wd_in[74]
    DIRECTION INPUT ;
    USE SIGNAL ;
    SHAPE ABUTMENT ;
    PORT
      LAYER metal2 ;
      RECT 10.605 0.000 10.675 0.210 ;
    END
  END rw0_wd_in[74]
  PIN rw0_wd_in[75]
    DIRECTION INPUT ;
    USE SIGNAL ;
    SHAPE ABUTMENT ;
    PORT
      LAYER metal2 ;
      RECT 11.555 0.000 11.625 0.210 ;
    END
  END rw0_wd_in[75]
  PIN rw0_wd_in[76]
    DIRECTION INPUT ;
    USE SIGNAL ;
    SHAPE ABUTMENT ;
    PORT
      LAYER metal2 ;
      RECT 12.505 0.000 12.575 0.210 ;
    END
  END rw0_wd_in[76]
  PIN rw0_wd_in[77]
    DIRECTION INPUT ;
    USE SIGNAL ;
    SHAPE ABUTMENT ;
    PORT
      LAYER metal2 ;
      RECT 13.455 0.000 13.525 0.210 ;
    END
  END rw0_wd_in[77]
  PIN rw0_wd_in[78]
    DIRECTION INPUT ;
    USE SIGNAL ;
    SHAPE ABUTMENT ;
    PORT
      LAYER metal2 ;
      RECT 14.405 0.000 14.475 0.210 ;
    END
  END rw0_wd_in[78]
  PIN rw0_wd_in[79]
    DIRECTION INPUT ;
    USE SIGNAL ;
    SHAPE ABUTMENT ;
    PORT
      LAYER metal2 ;
      RECT 15.355 0.000 15.425 0.210 ;
    END
  END rw0_wd_in[79]
  PIN rw0_wd_in[80]
    DIRECTION INPUT ;
    USE SIGNAL ;
    SHAPE ABUTMENT ;
    PORT
      LAYER metal2 ;
      RECT 16.305 0.000 16.375 0.210 ;
    END
  END rw0_wd_in[80]
  PIN rw0_wd_in[81]
    DIRECTION INPUT ;
    USE SIGNAL ;
    SHAPE ABUTMENT ;
    PORT
      LAYER metal2 ;
      RECT 17.255 0.000 17.325 0.210 ;
    END
  END rw0_wd_in[81]
  PIN rw0_wd_in[82]
    DIRECTION INPUT ;
    USE SIGNAL ;
    SHAPE ABUTMENT ;
    PORT
      LAYER metal2 ;
      RECT 18.205 0.000 18.275 0.210 ;
    END
  END rw0_wd_in[82]
  PIN rw0_wd_in[83]
    DIRECTION INPUT ;
    USE SIGNAL ;
    SHAPE ABUTMENT ;
    PORT
      LAYER metal2 ;
      RECT 19.155 0.000 19.225 0.210 ;
    END
  END rw0_wd_in[83]
  PIN rw0_wd_in[84]
    DIRECTION INPUT ;
    USE SIGNAL ;
    SHAPE ABUTMENT ;
    PORT
      LAYER metal2 ;
      RECT 20.105 0.000 20.175 0.210 ;
    END
  END rw0_wd_in[84]
  PIN rw0_wd_in[85]
    DIRECTION INPUT ;
    USE SIGNAL ;
    SHAPE ABUTMENT ;
    PORT
      LAYER metal2 ;
      RECT 21.055 0.000 21.125 0.210 ;
    END
  END rw0_wd_in[85]
  PIN rw0_wd_in[86]
    DIRECTION INPUT ;
    USE SIGNAL ;
    SHAPE ABUTMENT ;
    PORT
      LAYER metal2 ;
      RECT 22.005 0.000 22.075 0.210 ;
    END
  END rw0_wd_in[86]
  PIN rw0_wd_in[87]
    DIRECTION INPUT ;
    USE SIGNAL ;
    SHAPE ABUTMENT ;
    PORT
      LAYER metal2 ;
      RECT 22.955 0.000 23.025 0.210 ;
    END
  END rw0_wd_in[87]
  PIN rw0_wd_in[88]
    DIRECTION INPUT ;
    USE SIGNAL ;
    SHAPE ABUTMENT ;
    PORT
      LAYER metal2 ;
      RECT 23.905 0.000 23.975 0.210 ;
    END
  END rw0_wd_in[88]
  PIN rw0_wd_in[89]
    DIRECTION INPUT ;
    USE SIGNAL ;
    SHAPE ABUTMENT ;
    PORT
      LAYER metal2 ;
      RECT 24.855 0.000 24.925 0.210 ;
    END
  END rw0_wd_in[89]
  PIN rw0_wd_in[90]
    DIRECTION INPUT ;
    USE SIGNAL ;
    SHAPE ABUTMENT ;
    PORT
      LAYER metal2 ;
      RECT 25.805 0.000 25.875 0.210 ;
    END
  END rw0_wd_in[90]
  PIN rw0_wd_in[91]
    DIRECTION INPUT ;
    USE SIGNAL ;
    SHAPE ABUTMENT ;
    PORT
      LAYER metal2 ;
      RECT 26.755 0.000 26.825 0.210 ;
    END
  END rw0_wd_in[91]
  PIN rw0_wd_in[92]
    DIRECTION INPUT ;
    USE SIGNAL ;
    SHAPE ABUTMENT ;
    PORT
      LAYER metal2 ;
      RECT 27.705 0.000 27.775 0.210 ;
    END
  END rw0_wd_in[92]
  PIN rw0_wd_in[93]
    DIRECTION INPUT ;
    USE SIGNAL ;
    SHAPE ABUTMENT ;
    PORT
      LAYER metal2 ;
      RECT 28.655 0.000 28.725 0.210 ;
    END
  END rw0_wd_in[93]
  PIN rw0_wd_in[94]
    DIRECTION INPUT ;
    USE SIGNAL ;
    SHAPE ABUTMENT ;
    PORT
      LAYER metal2 ;
      RECT 29.605 0.000 29.675 0.210 ;
    END
  END rw0_wd_in[94]
  PIN rw0_wd_in[95]
    DIRECTION INPUT ;
    USE SIGNAL ;
    SHAPE ABUTMENT ;
    PORT
      LAYER metal2 ;
      RECT 30.555 0.000 30.625 0.210 ;
    END
  END rw0_wd_in[95]
  PIN rw0_wd_in[96]
    DIRECTION INPUT ;
    USE SIGNAL ;
    SHAPE ABUTMENT ;
    PORT
      LAYER metal2 ;
      RECT 31.505 0.000 31.575 0.210 ;
    END
  END rw0_wd_in[96]
  PIN rw0_wd_in[97]
    DIRECTION INPUT ;
    USE SIGNAL ;
    SHAPE ABUTMENT ;
    PORT
      LAYER metal2 ;
      RECT 32.455 0.000 32.525 0.210 ;
    END
  END rw0_wd_in[97]
  PIN rw0_wd_in[98]
    DIRECTION INPUT ;
    USE SIGNAL ;
    SHAPE ABUTMENT ;
    PORT
      LAYER metal2 ;
      RECT 33.405 0.000 33.475 0.210 ;
    END
  END rw0_wd_in[98]
  PIN rw0_wd_in[99]
    DIRECTION INPUT ;
    USE SIGNAL ;
    SHAPE ABUTMENT ;
    PORT
      LAYER metal2 ;
      RECT 34.355 0.000 34.425 0.210 ;
    END
  END rw0_wd_in[99]
  PIN rw0_wd_in[100]
    DIRECTION INPUT ;
    USE SIGNAL ;
    SHAPE ABUTMENT ;
    PORT
      LAYER metal2 ;
      RECT 35.305 0.000 35.375 0.210 ;
    END
  END rw0_wd_in[100]
  PIN rw0_wd_in[101]
    DIRECTION INPUT ;
    USE SIGNAL ;
    SHAPE ABUTMENT ;
    PORT
      LAYER metal2 ;
      RECT 36.255 0.000 36.325 0.210 ;
    END
  END rw0_wd_in[101]
  PIN rw0_wd_in[102]
    DIRECTION INPUT ;
    USE SIGNAL ;
    SHAPE ABUTMENT ;
    PORT
      LAYER metal2 ;
      RECT 37.205 0.000 37.275 0.210 ;
    END
  END rw0_wd_in[102]
  PIN rw0_wd_in[103]
    DIRECTION INPUT ;
    USE SIGNAL ;
    SHAPE ABUTMENT ;
    PORT
      LAYER metal2 ;
      RECT 38.155 0.000 38.225 0.210 ;
    END
  END rw0_wd_in[103]
  PIN rw0_wd_in[104]
    DIRECTION INPUT ;
    USE SIGNAL ;
    SHAPE ABUTMENT ;
    PORT
      LAYER metal2 ;
      RECT 39.105 0.000 39.175 0.210 ;
    END
  END rw0_wd_in[104]
  PIN rw0_wd_in[105]
    DIRECTION INPUT ;
    USE SIGNAL ;
    SHAPE ABUTMENT ;
    PORT
      LAYER metal2 ;
      RECT 40.055 0.000 40.125 0.210 ;
    END
  END rw0_wd_in[105]
  PIN rw0_wd_in[106]
    DIRECTION INPUT ;
    USE SIGNAL ;
    SHAPE ABUTMENT ;
    PORT
      LAYER metal2 ;
      RECT 41.005 0.000 41.075 0.210 ;
    END
  END rw0_wd_in[106]
  PIN rw0_wd_in[107]
    DIRECTION INPUT ;
    USE SIGNAL ;
    SHAPE ABUTMENT ;
    PORT
      LAYER metal2 ;
      RECT 41.955 0.000 42.025 0.210 ;
    END
  END rw0_wd_in[107]
  PIN rw0_wd_in[108]
    DIRECTION INPUT ;
    USE SIGNAL ;
    SHAPE ABUTMENT ;
    PORT
      LAYER metal2 ;
      RECT 42.905 0.000 42.975 0.210 ;
    END
  END rw0_wd_in[108]
  PIN rw0_wd_in[109]
    DIRECTION INPUT ;
    USE SIGNAL ;
    SHAPE ABUTMENT ;
    PORT
      LAYER metal2 ;
      RECT 43.855 0.000 43.925 0.210 ;
    END
  END rw0_wd_in[109]
  PIN rw0_wd_in[110]
    DIRECTION INPUT ;
    USE SIGNAL ;
    SHAPE ABUTMENT ;
    PORT
      LAYER metal2 ;
      RECT 44.805 0.000 44.875 0.210 ;
    END
  END rw0_wd_in[110]
  PIN rw0_wd_in[111]
    DIRECTION INPUT ;
    USE SIGNAL ;
    SHAPE ABUTMENT ;
    PORT
      LAYER metal2 ;
      RECT 45.755 0.000 45.825 0.210 ;
    END
  END rw0_wd_in[111]
  PIN rw0_wd_in[112]
    DIRECTION INPUT ;
    USE SIGNAL ;
    SHAPE ABUTMENT ;
    PORT
      LAYER metal2 ;
      RECT 46.705 0.000 46.775 0.210 ;
    END
  END rw0_wd_in[112]
  PIN rw0_wd_in[113]
    DIRECTION INPUT ;
    USE SIGNAL ;
    SHAPE ABUTMENT ;
    PORT
      LAYER metal2 ;
      RECT 47.655 0.000 47.725 0.210 ;
    END
  END rw0_wd_in[113]
  PIN rw0_wd_in[114]
    DIRECTION INPUT ;
    USE SIGNAL ;
    SHAPE ABUTMENT ;
    PORT
      LAYER metal2 ;
      RECT 48.605 0.000 48.675 0.210 ;
    END
  END rw0_wd_in[114]
  PIN rw0_wd_in[115]
    DIRECTION INPUT ;
    USE SIGNAL ;
    SHAPE ABUTMENT ;
    PORT
      LAYER metal2 ;
      RECT 49.555 0.000 49.625 0.210 ;
    END
  END rw0_wd_in[115]
  PIN rw0_wd_in[116]
    DIRECTION INPUT ;
    USE SIGNAL ;
    SHAPE ABUTMENT ;
    PORT
      LAYER metal2 ;
      RECT 50.505 0.000 50.575 0.210 ;
    END
  END rw0_wd_in[116]
  PIN rw0_wd_in[117]
    DIRECTION INPUT ;
    USE SIGNAL ;
    SHAPE ABUTMENT ;
    PORT
      LAYER metal2 ;
      RECT 51.455 0.000 51.525 0.210 ;
    END
  END rw0_wd_in[117]
  PIN rw0_wd_in[118]
    DIRECTION INPUT ;
    USE SIGNAL ;
    SHAPE ABUTMENT ;
    PORT
      LAYER metal2 ;
      RECT 52.405 0.000 52.475 0.210 ;
    END
  END rw0_wd_in[118]
  PIN rw0_wd_in[119]
    DIRECTION INPUT ;
    USE SIGNAL ;
    SHAPE ABUTMENT ;
    PORT
      LAYER metal2 ;
      RECT 53.355 0.000 53.425 0.210 ;
    END
  END rw0_wd_in[119]
  PIN rw0_wd_in[120]
    DIRECTION INPUT ;
    USE SIGNAL ;
    SHAPE ABUTMENT ;
    PORT
      LAYER metal2 ;
      RECT 54.305 0.000 54.375 0.210 ;
    END
  END rw0_wd_in[120]
  PIN rw0_wd_in[121]
    DIRECTION INPUT ;
    USE SIGNAL ;
    SHAPE ABUTMENT ;
    PORT
      LAYER metal2 ;
      RECT 55.255 0.000 55.325 0.210 ;
    END
  END rw0_wd_in[121]
  PIN rw0_wd_in[122]
    DIRECTION INPUT ;
    USE SIGNAL ;
    SHAPE ABUTMENT ;
    PORT
      LAYER metal2 ;
      RECT 56.205 0.000 56.275 0.210 ;
    END
  END rw0_wd_in[122]
  PIN rw0_wd_in[123]
    DIRECTION INPUT ;
    USE SIGNAL ;
    SHAPE ABUTMENT ;
    PORT
      LAYER metal2 ;
      RECT 57.155 0.000 57.225 0.210 ;
    END
  END rw0_wd_in[123]
  PIN rw0_wd_in[124]
    DIRECTION INPUT ;
    USE SIGNAL ;
    SHAPE ABUTMENT ;
    PORT
      LAYER metal2 ;
      RECT 58.105 0.000 58.175 0.210 ;
    END
  END rw0_wd_in[124]
  PIN rw0_wd_in[125]
    DIRECTION INPUT ;
    USE SIGNAL ;
    SHAPE ABUTMENT ;
    PORT
      LAYER metal2 ;
      RECT 59.055 0.000 59.125 0.210 ;
    END
  END rw0_wd_in[125]
  PIN rw0_wd_in[126]
    DIRECTION INPUT ;
    USE SIGNAL ;
    SHAPE ABUTMENT ;
    PORT
      LAYER metal2 ;
      RECT 60.005 0.000 60.075 0.210 ;
    END
  END rw0_wd_in[126]
  PIN rw0_wd_in[127]
    DIRECTION INPUT ;
    USE SIGNAL ;
    SHAPE ABUTMENT ;
    PORT
      LAYER metal2 ;
      RECT 60.955 0.000 61.025 0.210 ;
    END
  END rw0_wd_in[127]
  PIN rw0_rd_out[0]
    DIRECTION OUTPUT ;
    USE SIGNAL ;
    SHAPE ABUTMENT ;
    PORT
      LAYER metal2 ;
      RECT 61.905 0.000 61.975 0.210 ;
    END
  END rw0_rd_out[0]
  PIN rw0_rd_out[1]
    DIRECTION OUTPUT ;
    USE SIGNAL ;
    SHAPE ABUTMENT ;
    PORT
      LAYER metal2 ;
      RECT 62.855 0.000 62.925 0.210 ;
    END
  END rw0_rd_out[1]
  PIN rw0_rd_out[2]
    DIRECTION OUTPUT ;
    USE SIGNAL ;
    SHAPE ABUTMENT ;
    PORT
      LAYER metal2 ;
      RECT 63.805 0.000 63.875 0.210 ;
    END
  END rw0_rd_out[2]
  PIN rw0_rd_out[3]
    DIRECTION OUTPUT ;
    USE SIGNAL ;
    SHAPE ABUTMENT ;
    PORT
      LAYER metal2 ;
      RECT 64.755 0.000 64.825 0.210 ;
    END
  END rw0_rd_out[3]
  PIN rw0_rd_out[4]
    DIRECTION OUTPUT ;
    USE SIGNAL ;
    SHAPE ABUTMENT ;
    PORT
      LAYER metal2 ;
      RECT 65.705 0.000 65.775 0.210 ;
    END
  END rw0_rd_out[4]
  PIN rw0_rd_out[5]
    DIRECTION OUTPUT ;
    USE SIGNAL ;
    SHAPE ABUTMENT ;
    PORT
      LAYER metal2 ;
      RECT 66.655 0.000 66.725 0.210 ;
    END
  END rw0_rd_out[5]
  PIN rw0_rd_out[6]
    DIRECTION OUTPUT ;
    USE SIGNAL ;
    SHAPE ABUTMENT ;
    PORT
      LAYER metal2 ;
      RECT 67.605 0.000 67.675 0.210 ;
    END
  END rw0_rd_out[6]
  PIN rw0_rd_out[7]
    DIRECTION OUTPUT ;
    USE SIGNAL ;
    SHAPE ABUTMENT ;
    PORT
      LAYER metal2 ;
      RECT 68.555 0.000 68.625 0.210 ;
    END
  END rw0_rd_out[7]
  PIN rw0_rd_out[8]
    DIRECTION OUTPUT ;
    USE SIGNAL ;
    SHAPE ABUTMENT ;
    PORT
      LAYER metal2 ;
      RECT 69.505 0.000 69.575 0.210 ;
    END
  END rw0_rd_out[8]
  PIN rw0_rd_out[9]
    DIRECTION OUTPUT ;
    USE SIGNAL ;
    SHAPE ABUTMENT ;
    PORT
      LAYER metal2 ;
      RECT 70.455 0.000 70.525 0.210 ;
    END
  END rw0_rd_out[9]
  PIN rw0_rd_out[10]
    DIRECTION OUTPUT ;
    USE SIGNAL ;
    SHAPE ABUTMENT ;
    PORT
      LAYER metal2 ;
      RECT 71.405 0.000 71.475 0.210 ;
    END
  END rw0_rd_out[10]
  PIN rw0_rd_out[11]
    DIRECTION OUTPUT ;
    USE SIGNAL ;
    SHAPE ABUTMENT ;
    PORT
      LAYER metal2 ;
      RECT 72.355 0.000 72.425 0.210 ;
    END
  END rw0_rd_out[11]
  PIN rw0_rd_out[12]
    DIRECTION OUTPUT ;
    USE SIGNAL ;
    SHAPE ABUTMENT ;
    PORT
      LAYER metal2 ;
      RECT 73.305 0.000 73.375 0.210 ;
    END
  END rw0_rd_out[12]
  PIN rw0_rd_out[13]
    DIRECTION OUTPUT ;
    USE SIGNAL ;
    SHAPE ABUTMENT ;
    PORT
      LAYER metal2 ;
      RECT 74.255 0.000 74.325 0.210 ;
    END
  END rw0_rd_out[13]
  PIN rw0_rd_out[14]
    DIRECTION OUTPUT ;
    USE SIGNAL ;
    SHAPE ABUTMENT ;
    PORT
      LAYER metal2 ;
      RECT 75.205 0.000 75.275 0.210 ;
    END
  END rw0_rd_out[14]
  PIN rw0_rd_out[15]
    DIRECTION OUTPUT ;
    USE SIGNAL ;
    SHAPE ABUTMENT ;
    PORT
      LAYER metal2 ;
      RECT 76.155 0.000 76.225 0.210 ;
    END
  END rw0_rd_out[15]
  PIN rw0_rd_out[16]
    DIRECTION OUTPUT ;
    USE SIGNAL ;
    SHAPE ABUTMENT ;
    PORT
      LAYER metal2 ;
      RECT 77.105 0.000 77.175 0.210 ;
    END
  END rw0_rd_out[16]
  PIN rw0_rd_out[17]
    DIRECTION OUTPUT ;
    USE SIGNAL ;
    SHAPE ABUTMENT ;
    PORT
      LAYER metal2 ;
      RECT 78.055 0.000 78.125 0.210 ;
    END
  END rw0_rd_out[17]
  PIN rw0_rd_out[18]
    DIRECTION OUTPUT ;
    USE SIGNAL ;
    SHAPE ABUTMENT ;
    PORT
      LAYER metal2 ;
      RECT 79.005 0.000 79.075 0.210 ;
    END
  END rw0_rd_out[18]
  PIN rw0_rd_out[19]
    DIRECTION OUTPUT ;
    USE SIGNAL ;
    SHAPE ABUTMENT ;
    PORT
      LAYER metal2 ;
      RECT 79.955 0.000 80.025 0.210 ;
    END
  END rw0_rd_out[19]
  PIN rw0_rd_out[20]
    DIRECTION OUTPUT ;
    USE SIGNAL ;
    SHAPE ABUTMENT ;
    PORT
      LAYER metal2 ;
      RECT 80.905 0.000 80.975 0.210 ;
    END
  END rw0_rd_out[20]
  PIN rw0_rd_out[21]
    DIRECTION OUTPUT ;
    USE SIGNAL ;
    SHAPE ABUTMENT ;
    PORT
      LAYER metal2 ;
      RECT 81.855 0.000 81.925 0.210 ;
    END
  END rw0_rd_out[21]
  PIN rw0_rd_out[22]
    DIRECTION OUTPUT ;
    USE SIGNAL ;
    SHAPE ABUTMENT ;
    PORT
      LAYER metal2 ;
      RECT 82.805 0.000 82.875 0.210 ;
    END
  END rw0_rd_out[22]
  PIN rw0_rd_out[23]
    DIRECTION OUTPUT ;
    USE SIGNAL ;
    SHAPE ABUTMENT ;
    PORT
      LAYER metal2 ;
      RECT 83.755 0.000 83.825 0.210 ;
    END
  END rw0_rd_out[23]
  PIN rw0_rd_out[24]
    DIRECTION OUTPUT ;
    USE SIGNAL ;
    SHAPE ABUTMENT ;
    PORT
      LAYER metal2 ;
      RECT 84.705 0.000 84.775 0.210 ;
    END
  END rw0_rd_out[24]
  PIN rw0_rd_out[25]
    DIRECTION OUTPUT ;
    USE SIGNAL ;
    SHAPE ABUTMENT ;
    PORT
      LAYER metal2 ;
      RECT 85.655 0.000 85.725 0.210 ;
    END
  END rw0_rd_out[25]
  PIN rw0_rd_out[26]
    DIRECTION OUTPUT ;
    USE SIGNAL ;
    SHAPE ABUTMENT ;
    PORT
      LAYER metal2 ;
      RECT 86.605 0.000 86.675 0.210 ;
    END
  END rw0_rd_out[26]
  PIN rw0_rd_out[27]
    DIRECTION OUTPUT ;
    USE SIGNAL ;
    SHAPE ABUTMENT ;
    PORT
      LAYER metal2 ;
      RECT 87.555 0.000 87.625 0.210 ;
    END
  END rw0_rd_out[27]
  PIN rw0_rd_out[28]
    DIRECTION OUTPUT ;
    USE SIGNAL ;
    SHAPE ABUTMENT ;
    PORT
      LAYER metal2 ;
      RECT 88.505 0.000 88.575 0.210 ;
    END
  END rw0_rd_out[28]
  PIN rw0_rd_out[29]
    DIRECTION OUTPUT ;
    USE SIGNAL ;
    SHAPE ABUTMENT ;
    PORT
      LAYER metal2 ;
      RECT 89.455 0.000 89.525 0.210 ;
    END
  END rw0_rd_out[29]
  PIN rw0_rd_out[30]
    DIRECTION OUTPUT ;
    USE SIGNAL ;
    SHAPE ABUTMENT ;
    PORT
      LAYER metal2 ;
      RECT 90.405 0.000 90.475 0.210 ;
    END
  END rw0_rd_out[30]
  PIN rw0_rd_out[31]
    DIRECTION OUTPUT ;
    USE SIGNAL ;
    SHAPE ABUTMENT ;
    PORT
      LAYER metal2 ;
      RECT 91.355 0.000 91.425 0.210 ;
    END
  END rw0_rd_out[31]
  PIN rw0_rd_out[32]
    DIRECTION OUTPUT ;
    USE SIGNAL ;
    SHAPE ABUTMENT ;
    PORT
      LAYER metal2 ;
      RECT 92.305 0.000 92.375 0.210 ;
    END
  END rw0_rd_out[32]
  PIN rw0_rd_out[33]
    DIRECTION OUTPUT ;
    USE SIGNAL ;
    SHAPE ABUTMENT ;
    PORT
      LAYER metal2 ;
      RECT 93.255 0.000 93.325 0.210 ;
    END
  END rw0_rd_out[33]
  PIN rw0_rd_out[34]
    DIRECTION OUTPUT ;
    USE SIGNAL ;
    SHAPE ABUTMENT ;
    PORT
      LAYER metal2 ;
      RECT 94.205 0.000 94.275 0.210 ;
    END
  END rw0_rd_out[34]
  PIN rw0_rd_out[35]
    DIRECTION OUTPUT ;
    USE SIGNAL ;
    SHAPE ABUTMENT ;
    PORT
      LAYER metal2 ;
      RECT 95.155 0.000 95.225 0.210 ;
    END
  END rw0_rd_out[35]
  PIN rw0_rd_out[36]
    DIRECTION OUTPUT ;
    USE SIGNAL ;
    SHAPE ABUTMENT ;
    PORT
      LAYER metal2 ;
      RECT 96.105 0.000 96.175 0.210 ;
    END
  END rw0_rd_out[36]
  PIN rw0_rd_out[37]
    DIRECTION OUTPUT ;
    USE SIGNAL ;
    SHAPE ABUTMENT ;
    PORT
      LAYER metal2 ;
      RECT 97.055 0.000 97.125 0.210 ;
    END
  END rw0_rd_out[37]
  PIN rw0_rd_out[38]
    DIRECTION OUTPUT ;
    USE SIGNAL ;
    SHAPE ABUTMENT ;
    PORT
      LAYER metal2 ;
      RECT 98.005 0.000 98.075 0.210 ;
    END
  END rw0_rd_out[38]
  PIN rw0_rd_out[39]
    DIRECTION OUTPUT ;
    USE SIGNAL ;
    SHAPE ABUTMENT ;
    PORT
      LAYER metal2 ;
      RECT 98.955 0.000 99.025 0.210 ;
    END
  END rw0_rd_out[39]
  PIN rw0_rd_out[40]
    DIRECTION OUTPUT ;
    USE SIGNAL ;
    SHAPE ABUTMENT ;
    PORT
      LAYER metal2 ;
      RECT 99.905 0.000 99.975 0.210 ;
    END
  END rw0_rd_out[40]
  PIN rw0_rd_out[41]
    DIRECTION OUTPUT ;
    USE SIGNAL ;
    SHAPE ABUTMENT ;
    PORT
      LAYER metal2 ;
      RECT 100.855 0.000 100.925 0.210 ;
    END
  END rw0_rd_out[41]
  PIN rw0_rd_out[42]
    DIRECTION OUTPUT ;
    USE SIGNAL ;
    SHAPE ABUTMENT ;
    PORT
      LAYER metal2 ;
      RECT 101.805 0.000 101.875 0.210 ;
    END
  END rw0_rd_out[42]
  PIN rw0_rd_out[43]
    DIRECTION OUTPUT ;
    USE SIGNAL ;
    SHAPE ABUTMENT ;
    PORT
      LAYER metal2 ;
      RECT 102.755 0.000 102.825 0.210 ;
    END
  END rw0_rd_out[43]
  PIN rw0_rd_out[44]
    DIRECTION OUTPUT ;
    USE SIGNAL ;
    SHAPE ABUTMENT ;
    PORT
      LAYER metal2 ;
      RECT 103.705 0.000 103.775 0.210 ;
    END
  END rw0_rd_out[44]
  PIN rw0_rd_out[45]
    DIRECTION OUTPUT ;
    USE SIGNAL ;
    SHAPE ABUTMENT ;
    PORT
      LAYER metal2 ;
      RECT 104.655 0.000 104.725 0.210 ;
    END
  END rw0_rd_out[45]
  PIN rw0_rd_out[46]
    DIRECTION OUTPUT ;
    USE SIGNAL ;
    SHAPE ABUTMENT ;
    PORT
      LAYER metal2 ;
      RECT 105.605 0.000 105.675 0.210 ;
    END
  END rw0_rd_out[46]
  PIN rw0_rd_out[47]
    DIRECTION OUTPUT ;
    USE SIGNAL ;
    SHAPE ABUTMENT ;
    PORT
      LAYER metal2 ;
      RECT 106.555 0.000 106.625 0.210 ;
    END
  END rw0_rd_out[47]
  PIN rw0_rd_out[48]
    DIRECTION OUTPUT ;
    USE SIGNAL ;
    SHAPE ABUTMENT ;
    PORT
      LAYER metal2 ;
      RECT 107.505 0.000 107.575 0.210 ;
    END
  END rw0_rd_out[48]
  PIN rw0_rd_out[49]
    DIRECTION OUTPUT ;
    USE SIGNAL ;
    SHAPE ABUTMENT ;
    PORT
      LAYER metal2 ;
      RECT 108.455 0.000 108.525 0.210 ;
    END
  END rw0_rd_out[49]
  PIN rw0_rd_out[50]
    DIRECTION OUTPUT ;
    USE SIGNAL ;
    SHAPE ABUTMENT ;
    PORT
      LAYER metal2 ;
      RECT 109.405 0.000 109.475 0.210 ;
    END
  END rw0_rd_out[50]
  PIN rw0_rd_out[51]
    DIRECTION OUTPUT ;
    USE SIGNAL ;
    SHAPE ABUTMENT ;
    PORT
      LAYER metal2 ;
      RECT 110.355 0.000 110.425 0.210 ;
    END
  END rw0_rd_out[51]
  PIN rw0_rd_out[52]
    DIRECTION OUTPUT ;
    USE SIGNAL ;
    SHAPE ABUTMENT ;
    PORT
      LAYER metal2 ;
      RECT 111.305 0.000 111.375 0.210 ;
    END
  END rw0_rd_out[52]
  PIN rw0_rd_out[53]
    DIRECTION OUTPUT ;
    USE SIGNAL ;
    SHAPE ABUTMENT ;
    PORT
      LAYER metal2 ;
      RECT 112.255 0.000 112.325 0.210 ;
    END
  END rw0_rd_out[53]
  PIN rw0_rd_out[54]
    DIRECTION OUTPUT ;
    USE SIGNAL ;
    SHAPE ABUTMENT ;
    PORT
      LAYER metal2 ;
      RECT 113.205 0.000 113.275 0.210 ;
    END
  END rw0_rd_out[54]
  PIN rw0_rd_out[55]
    DIRECTION OUTPUT ;
    USE SIGNAL ;
    SHAPE ABUTMENT ;
    PORT
      LAYER metal2 ;
      RECT 114.155 0.000 114.225 0.210 ;
    END
  END rw0_rd_out[55]
  PIN rw0_rd_out[56]
    DIRECTION OUTPUT ;
    USE SIGNAL ;
    SHAPE ABUTMENT ;
    PORT
      LAYER metal2 ;
      RECT 115.105 0.000 115.175 0.210 ;
    END
  END rw0_rd_out[56]
  PIN rw0_rd_out[57]
    DIRECTION OUTPUT ;
    USE SIGNAL ;
    SHAPE ABUTMENT ;
    PORT
      LAYER metal2 ;
      RECT 116.055 0.000 116.125 0.210 ;
    END
  END rw0_rd_out[57]
  PIN rw0_rd_out[58]
    DIRECTION OUTPUT ;
    USE SIGNAL ;
    SHAPE ABUTMENT ;
    PORT
      LAYER metal2 ;
      RECT 117.005 0.000 117.075 0.210 ;
    END
  END rw0_rd_out[58]
  PIN rw0_rd_out[59]
    DIRECTION OUTPUT ;
    USE SIGNAL ;
    SHAPE ABUTMENT ;
    PORT
      LAYER metal2 ;
      RECT 117.955 0.000 118.025 0.210 ;
    END
  END rw0_rd_out[59]
  PIN rw0_rd_out[60]
    DIRECTION OUTPUT ;
    USE SIGNAL ;
    SHAPE ABUTMENT ;
    PORT
      LAYER metal2 ;
      RECT 118.905 0.000 118.975 0.210 ;
    END
  END rw0_rd_out[60]
  PIN rw0_rd_out[61]
    DIRECTION OUTPUT ;
    USE SIGNAL ;
    SHAPE ABUTMENT ;
    PORT
      LAYER metal2 ;
      RECT 119.855 0.000 119.925 0.210 ;
    END
  END rw0_rd_out[61]
  PIN rw0_rd_out[62]
    DIRECTION OUTPUT ;
    USE SIGNAL ;
    SHAPE ABUTMENT ;
    PORT
      LAYER metal2 ;
      RECT 120.805 0.000 120.875 0.210 ;
    END
  END rw0_rd_out[62]
  PIN rw0_rd_out[63]
    DIRECTION OUTPUT ;
    USE SIGNAL ;
    SHAPE ABUTMENT ;
    PORT
      LAYER metal2 ;
      RECT 121.755 0.000 121.825 0.210 ;
    END
  END rw0_rd_out[63]
  PIN rw0_rd_out[64]
    DIRECTION OUTPUT ;
    USE SIGNAL ;
    SHAPE ABUTMENT ;
    PORT
      LAYER metal2 ;
      RECT 49.745 237.790 49.815 238.000 ;
    END
  END rw0_rd_out[64]
  PIN rw0_rd_out[65]
    DIRECTION OUTPUT ;
    USE SIGNAL ;
    SHAPE ABUTMENT ;
    PORT
      LAYER metal2 ;
      RECT 50.505 237.790 50.575 238.000 ;
    END
  END rw0_rd_out[65]
  PIN rw0_rd_out[66]
    DIRECTION OUTPUT ;
    USE SIGNAL ;
    SHAPE ABUTMENT ;
    PORT
      LAYER metal2 ;
      RECT 51.265 237.790 51.335 238.000 ;
    END
  END rw0_rd_out[66]
  PIN rw0_rd_out[67]
    DIRECTION OUTPUT ;
    USE SIGNAL ;
    SHAPE ABUTMENT ;
    PORT
      LAYER metal2 ;
      RECT 52.025 237.790 52.095 238.000 ;
    END
  END rw0_rd_out[67]
  PIN rw0_rd_out[68]
    DIRECTION OUTPUT ;
    USE SIGNAL ;
    SHAPE ABUTMENT ;
    PORT
      LAYER metal2 ;
      RECT 52.785 237.790 52.855 238.000 ;
    END
  END rw0_rd_out[68]
  PIN rw0_rd_out[69]
    DIRECTION OUTPUT ;
    USE SIGNAL ;
    SHAPE ABUTMENT ;
    PORT
      LAYER metal2 ;
      RECT 53.545 237.790 53.615 238.000 ;
    END
  END rw0_rd_out[69]
  PIN rw0_rd_out[70]
    DIRECTION OUTPUT ;
    USE SIGNAL ;
    SHAPE ABUTMENT ;
    PORT
      LAYER metal2 ;
      RECT 54.305 237.790 54.375 238.000 ;
    END
  END rw0_rd_out[70]
  PIN rw0_rd_out[71]
    DIRECTION OUTPUT ;
    USE SIGNAL ;
    SHAPE ABUTMENT ;
    PORT
      LAYER metal2 ;
      RECT 55.065 237.790 55.135 238.000 ;
    END
  END rw0_rd_out[71]
  PIN rw0_rd_out[72]
    DIRECTION OUTPUT ;
    USE SIGNAL ;
    SHAPE ABUTMENT ;
    PORT
      LAYER metal2 ;
      RECT 55.825 237.790 55.895 238.000 ;
    END
  END rw0_rd_out[72]
  PIN rw0_rd_out[73]
    DIRECTION OUTPUT ;
    USE SIGNAL ;
    SHAPE ABUTMENT ;
    PORT
      LAYER metal2 ;
      RECT 56.585 237.790 56.655 238.000 ;
    END
  END rw0_rd_out[73]
  PIN rw0_rd_out[74]
    DIRECTION OUTPUT ;
    USE SIGNAL ;
    SHAPE ABUTMENT ;
    PORT
      LAYER metal2 ;
      RECT 57.345 237.790 57.415 238.000 ;
    END
  END rw0_rd_out[74]
  PIN rw0_rd_out[75]
    DIRECTION OUTPUT ;
    USE SIGNAL ;
    SHAPE ABUTMENT ;
    PORT
      LAYER metal2 ;
      RECT 58.105 237.790 58.175 238.000 ;
    END
  END rw0_rd_out[75]
  PIN rw0_rd_out[76]
    DIRECTION OUTPUT ;
    USE SIGNAL ;
    SHAPE ABUTMENT ;
    PORT
      LAYER metal2 ;
      RECT 58.865 237.790 58.935 238.000 ;
    END
  END rw0_rd_out[76]
  PIN rw0_rd_out[77]
    DIRECTION OUTPUT ;
    USE SIGNAL ;
    SHAPE ABUTMENT ;
    PORT
      LAYER metal2 ;
      RECT 59.625 237.790 59.695 238.000 ;
    END
  END rw0_rd_out[77]
  PIN rw0_rd_out[78]
    DIRECTION OUTPUT ;
    USE SIGNAL ;
    SHAPE ABUTMENT ;
    PORT
      LAYER metal2 ;
      RECT 60.385 237.790 60.455 238.000 ;
    END
  END rw0_rd_out[78]
  PIN rw0_rd_out[79]
    DIRECTION OUTPUT ;
    USE SIGNAL ;
    SHAPE ABUTMENT ;
    PORT
      LAYER metal2 ;
      RECT 61.145 237.790 61.215 238.000 ;
    END
  END rw0_rd_out[79]
  PIN rw0_rd_out[80]
    DIRECTION OUTPUT ;
    USE SIGNAL ;
    SHAPE ABUTMENT ;
    PORT
      LAYER metal2 ;
      RECT 61.905 237.790 61.975 238.000 ;
    END
  END rw0_rd_out[80]
  PIN rw0_rd_out[81]
    DIRECTION OUTPUT ;
    USE SIGNAL ;
    SHAPE ABUTMENT ;
    PORT
      LAYER metal2 ;
      RECT 62.665 237.790 62.735 238.000 ;
    END
  END rw0_rd_out[81]
  PIN rw0_rd_out[82]
    DIRECTION OUTPUT ;
    USE SIGNAL ;
    SHAPE ABUTMENT ;
    PORT
      LAYER metal2 ;
      RECT 63.425 237.790 63.495 238.000 ;
    END
  END rw0_rd_out[82]
  PIN rw0_rd_out[83]
    DIRECTION OUTPUT ;
    USE SIGNAL ;
    SHAPE ABUTMENT ;
    PORT
      LAYER metal2 ;
      RECT 64.185 237.790 64.255 238.000 ;
    END
  END rw0_rd_out[83]
  PIN rw0_rd_out[84]
    DIRECTION OUTPUT ;
    USE SIGNAL ;
    SHAPE ABUTMENT ;
    PORT
      LAYER metal2 ;
      RECT 64.945 237.790 65.015 238.000 ;
    END
  END rw0_rd_out[84]
  PIN rw0_rd_out[85]
    DIRECTION OUTPUT ;
    USE SIGNAL ;
    SHAPE ABUTMENT ;
    PORT
      LAYER metal2 ;
      RECT 65.705 237.790 65.775 238.000 ;
    END
  END rw0_rd_out[85]
  PIN rw0_rd_out[86]
    DIRECTION OUTPUT ;
    USE SIGNAL ;
    SHAPE ABUTMENT ;
    PORT
      LAYER metal2 ;
      RECT 66.465 237.790 66.535 238.000 ;
    END
  END rw0_rd_out[86]
  PIN rw0_rd_out[87]
    DIRECTION OUTPUT ;
    USE SIGNAL ;
    SHAPE ABUTMENT ;
    PORT
      LAYER metal2 ;
      RECT 67.225 237.790 67.295 238.000 ;
    END
  END rw0_rd_out[87]
  PIN rw0_rd_out[88]
    DIRECTION OUTPUT ;
    USE SIGNAL ;
    SHAPE ABUTMENT ;
    PORT
      LAYER metal2 ;
      RECT 67.985 237.790 68.055 238.000 ;
    END
  END rw0_rd_out[88]
  PIN rw0_rd_out[89]
    DIRECTION OUTPUT ;
    USE SIGNAL ;
    SHAPE ABUTMENT ;
    PORT
      LAYER metal2 ;
      RECT 68.745 237.790 68.815 238.000 ;
    END
  END rw0_rd_out[89]
  PIN rw0_rd_out[90]
    DIRECTION OUTPUT ;
    USE SIGNAL ;
    SHAPE ABUTMENT ;
    PORT
      LAYER metal2 ;
      RECT 69.505 237.790 69.575 238.000 ;
    END
  END rw0_rd_out[90]
  PIN rw0_rd_out[91]
    DIRECTION OUTPUT ;
    USE SIGNAL ;
    SHAPE ABUTMENT ;
    PORT
      LAYER metal2 ;
      RECT 70.265 237.790 70.335 238.000 ;
    END
  END rw0_rd_out[91]
  PIN rw0_rd_out[92]
    DIRECTION OUTPUT ;
    USE SIGNAL ;
    SHAPE ABUTMENT ;
    PORT
      LAYER metal2 ;
      RECT 71.025 237.790 71.095 238.000 ;
    END
  END rw0_rd_out[92]
  PIN rw0_rd_out[93]
    DIRECTION OUTPUT ;
    USE SIGNAL ;
    SHAPE ABUTMENT ;
    PORT
      LAYER metal2 ;
      RECT 71.785 237.790 71.855 238.000 ;
    END
  END rw0_rd_out[93]
  PIN rw0_rd_out[94]
    DIRECTION OUTPUT ;
    USE SIGNAL ;
    SHAPE ABUTMENT ;
    PORT
      LAYER metal2 ;
      RECT 72.545 237.790 72.615 238.000 ;
    END
  END rw0_rd_out[94]
  PIN rw0_rd_out[95]
    DIRECTION OUTPUT ;
    USE SIGNAL ;
    SHAPE ABUTMENT ;
    PORT
      LAYER metal2 ;
      RECT 73.305 237.790 73.375 238.000 ;
    END
  END rw0_rd_out[95]
  PIN rw0_rd_out[96]
    DIRECTION OUTPUT ;
    USE SIGNAL ;
    SHAPE ABUTMENT ;
    PORT
      LAYER metal2 ;
      RECT 74.065 237.790 74.135 238.000 ;
    END
  END rw0_rd_out[96]
  PIN rw0_rd_out[97]
    DIRECTION OUTPUT ;
    USE SIGNAL ;
    SHAPE ABUTMENT ;
    PORT
      LAYER metal2 ;
      RECT 74.825 237.790 74.895 238.000 ;
    END
  END rw0_rd_out[97]
  PIN rw0_rd_out[98]
    DIRECTION OUTPUT ;
    USE SIGNAL ;
    SHAPE ABUTMENT ;
    PORT
      LAYER metal2 ;
      RECT 75.585 237.790 75.655 238.000 ;
    END
  END rw0_rd_out[98]
  PIN rw0_rd_out[99]
    DIRECTION OUTPUT ;
    USE SIGNAL ;
    SHAPE ABUTMENT ;
    PORT
      LAYER metal2 ;
      RECT 76.345 237.790 76.415 238.000 ;
    END
  END rw0_rd_out[99]
  PIN rw0_rd_out[100]
    DIRECTION OUTPUT ;
    USE SIGNAL ;
    SHAPE ABUTMENT ;
    PORT
      LAYER metal2 ;
      RECT 77.105 237.790 77.175 238.000 ;
    END
  END rw0_rd_out[100]
  PIN rw0_rd_out[101]
    DIRECTION OUTPUT ;
    USE SIGNAL ;
    SHAPE ABUTMENT ;
    PORT
      LAYER metal2 ;
      RECT 77.865 237.790 77.935 238.000 ;
    END
  END rw0_rd_out[101]
  PIN rw0_rd_out[102]
    DIRECTION OUTPUT ;
    USE SIGNAL ;
    SHAPE ABUTMENT ;
    PORT
      LAYER metal2 ;
      RECT 78.625 237.790 78.695 238.000 ;
    END
  END rw0_rd_out[102]
  PIN rw0_rd_out[103]
    DIRECTION OUTPUT ;
    USE SIGNAL ;
    SHAPE ABUTMENT ;
    PORT
      LAYER metal2 ;
      RECT 79.385 237.790 79.455 238.000 ;
    END
  END rw0_rd_out[103]
  PIN rw0_rd_out[104]
    DIRECTION OUTPUT ;
    USE SIGNAL ;
    SHAPE ABUTMENT ;
    PORT
      LAYER metal2 ;
      RECT 80.145 237.790 80.215 238.000 ;
    END
  END rw0_rd_out[104]
  PIN rw0_rd_out[105]
    DIRECTION OUTPUT ;
    USE SIGNAL ;
    SHAPE ABUTMENT ;
    PORT
      LAYER metal2 ;
      RECT 80.905 237.790 80.975 238.000 ;
    END
  END rw0_rd_out[105]
  PIN rw0_rd_out[106]
    DIRECTION OUTPUT ;
    USE SIGNAL ;
    SHAPE ABUTMENT ;
    PORT
      LAYER metal2 ;
      RECT 81.665 237.790 81.735 238.000 ;
    END
  END rw0_rd_out[106]
  PIN rw0_rd_out[107]
    DIRECTION OUTPUT ;
    USE SIGNAL ;
    SHAPE ABUTMENT ;
    PORT
      LAYER metal2 ;
      RECT 82.425 237.790 82.495 238.000 ;
    END
  END rw0_rd_out[107]
  PIN rw0_rd_out[108]
    DIRECTION OUTPUT ;
    USE SIGNAL ;
    SHAPE ABUTMENT ;
    PORT
      LAYER metal2 ;
      RECT 83.185 237.790 83.255 238.000 ;
    END
  END rw0_rd_out[108]
  PIN rw0_rd_out[109]
    DIRECTION OUTPUT ;
    USE SIGNAL ;
    SHAPE ABUTMENT ;
    PORT
      LAYER metal2 ;
      RECT 83.945 237.790 84.015 238.000 ;
    END
  END rw0_rd_out[109]
  PIN rw0_rd_out[110]
    DIRECTION OUTPUT ;
    USE SIGNAL ;
    SHAPE ABUTMENT ;
    PORT
      LAYER metal2 ;
      RECT 84.705 237.790 84.775 238.000 ;
    END
  END rw0_rd_out[110]
  PIN rw0_rd_out[111]
    DIRECTION OUTPUT ;
    USE SIGNAL ;
    SHAPE ABUTMENT ;
    PORT
      LAYER metal2 ;
      RECT 85.465 237.790 85.535 238.000 ;
    END
  END rw0_rd_out[111]
  PIN rw0_rd_out[112]
    DIRECTION OUTPUT ;
    USE SIGNAL ;
    SHAPE ABUTMENT ;
    PORT
      LAYER metal2 ;
      RECT 86.225 237.790 86.295 238.000 ;
    END
  END rw0_rd_out[112]
  PIN rw0_rd_out[113]
    DIRECTION OUTPUT ;
    USE SIGNAL ;
    SHAPE ABUTMENT ;
    PORT
      LAYER metal2 ;
      RECT 86.985 237.790 87.055 238.000 ;
    END
  END rw0_rd_out[113]
  PIN rw0_rd_out[114]
    DIRECTION OUTPUT ;
    USE SIGNAL ;
    SHAPE ABUTMENT ;
    PORT
      LAYER metal2 ;
      RECT 87.745 237.790 87.815 238.000 ;
    END
  END rw0_rd_out[114]
  PIN rw0_rd_out[115]
    DIRECTION OUTPUT ;
    USE SIGNAL ;
    SHAPE ABUTMENT ;
    PORT
      LAYER metal2 ;
      RECT 88.505 237.790 88.575 238.000 ;
    END
  END rw0_rd_out[115]
  PIN rw0_rd_out[116]
    DIRECTION OUTPUT ;
    USE SIGNAL ;
    SHAPE ABUTMENT ;
    PORT
      LAYER metal2 ;
      RECT 89.265 237.790 89.335 238.000 ;
    END
  END rw0_rd_out[116]
  PIN rw0_rd_out[117]
    DIRECTION OUTPUT ;
    USE SIGNAL ;
    SHAPE ABUTMENT ;
    PORT
      LAYER metal2 ;
      RECT 90.025 237.790 90.095 238.000 ;
    END
  END rw0_rd_out[117]
  PIN rw0_rd_out[118]
    DIRECTION OUTPUT ;
    USE SIGNAL ;
    SHAPE ABUTMENT ;
    PORT
      LAYER metal2 ;
      RECT 90.785 237.790 90.855 238.000 ;
    END
  END rw0_rd_out[118]
  PIN rw0_rd_out[119]
    DIRECTION OUTPUT ;
    USE SIGNAL ;
    SHAPE ABUTMENT ;
    PORT
      LAYER metal2 ;
      RECT 91.545 237.790 91.615 238.000 ;
    END
  END rw0_rd_out[119]
  PIN rw0_rd_out[120]
    DIRECTION OUTPUT ;
    USE SIGNAL ;
    SHAPE ABUTMENT ;
    PORT
      LAYER metal2 ;
      RECT 92.305 237.790 92.375 238.000 ;
    END
  END rw0_rd_out[120]
  PIN rw0_rd_out[121]
    DIRECTION OUTPUT ;
    USE SIGNAL ;
    SHAPE ABUTMENT ;
    PORT
      LAYER metal2 ;
      RECT 93.065 237.790 93.135 238.000 ;
    END
  END rw0_rd_out[121]
  PIN rw0_rd_out[122]
    DIRECTION OUTPUT ;
    USE SIGNAL ;
    SHAPE ABUTMENT ;
    PORT
      LAYER metal2 ;
      RECT 93.825 237.790 93.895 238.000 ;
    END
  END rw0_rd_out[122]
  PIN rw0_rd_out[123]
    DIRECTION OUTPUT ;
    USE SIGNAL ;
    SHAPE ABUTMENT ;
    PORT
      LAYER metal2 ;
      RECT 94.585 237.790 94.655 238.000 ;
    END
  END rw0_rd_out[123]
  PIN rw0_rd_out[124]
    DIRECTION OUTPUT ;
    USE SIGNAL ;
    SHAPE ABUTMENT ;
    PORT
      LAYER metal2 ;
      RECT 95.345 237.790 95.415 238.000 ;
    END
  END rw0_rd_out[124]
  PIN rw0_rd_out[125]
    DIRECTION OUTPUT ;
    USE SIGNAL ;
    SHAPE ABUTMENT ;
    PORT
      LAYER metal2 ;
      RECT 96.105 237.790 96.175 238.000 ;
    END
  END rw0_rd_out[125]
  PIN rw0_rd_out[126]
    DIRECTION OUTPUT ;
    USE SIGNAL ;
    SHAPE ABUTMENT ;
    PORT
      LAYER metal2 ;
      RECT 96.865 237.790 96.935 238.000 ;
    END
  END rw0_rd_out[126]
  PIN rw0_rd_out[127]
    DIRECTION OUTPUT ;
    USE SIGNAL ;
    SHAPE ABUTMENT ;
    PORT
      LAYER metal2 ;
      RECT 97.625 237.790 97.695 238.000 ;
    END
  END rw0_rd_out[127]
  PIN rw0_addr_in[0]
    DIRECTION INPUT ;
    USE SIGNAL ;
    SHAPE ABUTMENT ;
    PORT
      LAYER metal3 ;
      RECT 0.000 215.845 0.210 215.915 ;
    END
  END rw0_addr_in[0]
  PIN rw0_addr_in[1]
    DIRECTION INPUT ;
    USE SIGNAL ;
    SHAPE ABUTMENT ;
    PORT
      LAYER metal3 ;
      RECT 0.000 219.205 0.210 219.275 ;
    END
  END rw0_addr_in[1]
  PIN rw0_addr_in[2]
    DIRECTION INPUT ;
    USE SIGNAL ;
    SHAPE ABUTMENT ;
    PORT
      LAYER metal3 ;
      RECT 0.000 222.565 0.210 222.635 ;
    END
  END rw0_addr_in[2]
  PIN rw0_addr_in[3]
    DIRECTION INPUT ;
    USE SIGNAL ;
    SHAPE ABUTMENT ;
    PORT
      LAYER metal3 ;
      RECT 0.000 225.925 0.210 225.995 ;
    END
  END rw0_addr_in[3]
  PIN rw0_addr_in[4]
    DIRECTION INPUT ;
    USE SIGNAL ;
    SHAPE ABUTMENT ;
    PORT
      LAYER metal3 ;
      RECT 124.240 215.845 124.450 215.915 ;
    END
  END rw0_addr_in[4]
  PIN rw0_addr_in[5]
    DIRECTION INPUT ;
    USE SIGNAL ;
    SHAPE ABUTMENT ;
    PORT
      LAYER metal3 ;
      RECT 124.240 219.205 124.450 219.275 ;
    END
  END rw0_addr_in[5]
  PIN rw0_addr_in[6]
    DIRECTION INPUT ;
    USE SIGNAL ;
    SHAPE ABUTMENT ;
    PORT
      LAYER metal3 ;
      RECT 124.240 222.565 124.450 222.635 ;
    END
  END rw0_addr_in[6]
  PIN rw0_addr_in[7]
    DIRECTION INPUT ;
    USE SIGNAL ;
    SHAPE ABUTMENT ;
    PORT
      LAYER metal3 ;
      RECT 124.240 225.925 124.450 225.995 ;
    END
  END rw0_addr_in[7]
  PIN rw0_we_in
    DIRECTION INPUT ;
    USE SIGNAL ;
    SHAPE ABUTMENT ;
    PORT
      LAYER metal2 ;
      RECT 98.385 237.790 98.455 238.000 ;
    END
  END rw0_we_in
  PIN rw0_ce_in
    DIRECTION INPUT ;
    USE SIGNAL ;
    SHAPE ABUTMENT ;
    PORT
      LAYER metal2 ;
      RECT 99.145 237.790 99.215 238.000 ;
    END
  END rw0_ce_in
  PIN rw0_clk
    DIRECTION INPUT ;
    USE SIGNAL ;
    SHAPE ABUTMENT ;
    PORT
      LAYER metal2 ;
      RECT 99.905 237.790 99.975 238.000 ;
    END
  END rw0_clk
  PIN VSS
    DIRECTION INOUT ;
    USE GROUND ;
    PORT
      LAYER metal4 ;
      RECT 1.000 0.840 1.280 237.160 ;
      RECT 3.240 0.840 3.520 237.160 ;
      RECT 5.480 0.840 5.760 237.160 ;
      RECT 7.720 0.840 8.000 237.160 ;
      RECT 9.960 0.840 10.240 237.160 ;
      RECT 12.200 0.840 12.480 237.160 ;
      RECT 14.440 0.840 14.720 237.160 ;
      RECT 16.680 0.840 16.960 237.160 ;
      RECT 18.920 0.840 19.200 237.160 ;
      RECT 21.160 0.840 21.440 237.160 ;
      RECT 23.400 0.840 23.680 237.160 ;
      RECT 25.640 0.840 25.920 237.160 ;
      RECT 27.880 0.840 28.160 237.160 ;
      RECT 30.120 0.840 30.400 237.160 ;
      RECT 32.360 0.840 32.640 237.160 ;
      RECT 34.600 0.840 34.880 237.160 ;
      RECT 36.840 0.840 37.120 237.160 ;
      RECT 39.080 0.840 39.360 237.160 ;
      RECT 41.320 0.840 41.600 237.160 ;
      RECT 43.560 0.840 43.840 237.160 ;
      RECT 45.800 0.840 46.080 237.160 ;
      RECT 48.040 0.840 48.320 237.160 ;
      RECT 50.280 0.840 50.560 237.160 ;
      RECT 52.520 0.840 52.800 237.160 ;
      RECT 54.760 0.840 55.040 237.160 ;
      RECT 57.000 0.840 57.280 237.160 ;
      RECT 59.240 0.840 59.520 237.160 ;
      RECT 61.480 0.840 61.760 237.160 ;
      RECT 63.720 0.840 64.000 237.160 ;
      RECT 65.960 0.840 66.240 237.160 ;
      RECT 68.200 0.840 68.480 237.160 ;
      RECT 70.440 0.840 70.720 237.160 ;
      RECT 72.680 0.840 72.960 237.160 ;
      RECT 74.920 0.840 75.200 237.160 ;
      RECT 77.160 0.840 77.440 237.160 ;
      RECT 79.400 0.840 79.680 237.160 ;
      RECT 81.640 0.840 81.920 237.160 ;
      RECT 83.880 0.840 84.160 237.160 ;
      RECT 86.120 0.840 86.400 237.160 ;
      RECT 88.360 0.840 88.640 237.160 ;
      RECT 90.600 0.840 90.880 237.160 ;
      RECT 92.840 0.840 93.120 237.160 ;
      RECT 95.080 0.840 95.360 237.160 ;
      RECT 97.320 0.840 97.600 237.160 ;
      RECT 99.560 0.840 99.840 237.160 ;
      RECT 101.800 0.840 102.080 237.160 ;
      RECT 104.040 0.840 104.320 237.160 ;
      RECT 106.280 0.840 106.560 237.160 ;
      RECT 108.520 0.840 108.800 237.160 ;
      RECT 110.760 0.840 111.040 237.160 ;
      RECT 113.000 0.840 113.280 237.160 ;
      RECT 115.240 0.840 115.520 237.160 ;
      RECT 117.480 0.840 117.760 237.160 ;
      RECT 119.720 0.840 120.000 237.160 ;
      RECT 121.960 0.840 122.240 237.160 ;
    END
  END VSS
  PIN VDD
    DIRECTION INOUT ;
    USE POWER ;
    PORT
      LAYER metal4 ;
      RECT 2.120 0.840 2.400 237.160 ;
      RECT 4.360 0.840 4.640 237.160 ;
      RECT 6.600 0.840 6.880 237.160 ;
      RECT 8.840 0.840 9.120 237.160 ;
      RECT 11.080 0.840 11.360 237.160 ;
      RECT 13.320 0.840 13.600 237.160 ;
      RECT 15.560 0.840 15.840 237.160 ;
      RECT 17.800 0.840 18.080 237.160 ;
      RECT 20.040 0.840 20.320 237.160 ;
      RECT 22.280 0.840 22.560 237.160 ;
      RECT 24.520 0.840 24.800 237.160 ;
      RECT 26.760 0.840 27.040 237.160 ;
      RECT 29.000 0.840 29.280 237.160 ;
      RECT 31.240 0.840 31.520 237.160 ;
      RECT 33.480 0.840 33.760 237.160 ;
      RECT 35.720 0.840 36.000 237.160 ;
      RECT 37.960 0.840 38.240 237.160 ;
      RECT 40.200 0.840 40.480 237.160 ;
      RECT 42.440 0.840 42.720 237.160 ;
      RECT 44.680 0.840 44.960 237.160 ;
      RECT 46.920 0.840 47.200 237.160 ;
      RECT 49.160 0.840 49.440 237.160 ;
      RECT 51.400 0.840 51.680 237.160 ;
      RECT 53.640 0.840 53.920 237.160 ;
      RECT 55.880 0.840 56.160 237.160 ;
      RECT 58.120 0.840 58.400 237.160 ;
      RECT 60.360 0.840 60.640 237.160 ;
      RECT 62.600 0.840 62.880 237.160 ;
      RECT 64.840 0.840 65.120 237.160 ;
      RECT 67.080 0.840 67.360 237.160 ;
      RECT 69.320 0.840 69.600 237.160 ;
      RECT 71.560 0.840 71.840 237.160 ;
      RECT 73.800 0.840 74.080 237.160 ;
      RECT 76.040 0.840 76.320 237.160 ;
      RECT 78.280 0.840 78.560 237.160 ;
      RECT 80.520 0.840 80.800 237.160 ;
      RECT 82.760 0.840 83.040 237.160 ;
      RECT 85.000 0.840 85.280 237.160 ;
      RECT 87.240 0.840 87.520 237.160 ;
      RECT 89.480 0.840 89.760 237.160 ;
      RECT 91.720 0.840 92.000 237.160 ;
      RECT 93.960 0.840 94.240 237.160 ;
      RECT 96.200 0.840 96.480 237.160 ;
      RECT 98.440 0.840 98.720 237.160 ;
      RECT 100.680 0.840 100.960 237.160 ;
      RECT 102.920 0.840 103.200 237.160 ;
      RECT 105.160 0.840 105.440 237.160 ;
      RECT 107.400 0.840 107.680 237.160 ;
      RECT 109.640 0.840 109.920 237.160 ;
      RECT 111.880 0.840 112.160 237.160 ;
      RECT 114.120 0.840 114.400 237.160 ;
      RECT 116.360 0.840 116.640 237.160 ;
      RECT 118.600 0.840 118.880 237.160 ;
      RECT 120.840 0.840 121.120 237.160 ;
      RECT 123.080 0.840 123.360 237.160 ;
    END
  END VDD
  OBS
    LAYER metal1 ;
    RECT 0 0 124.450 238.000 ;
    LAYER metal2 ;
    RECT 0 0 124.450 238.000 ;
    LAYER metal3 ;
    RECT 0 0 124.450 238.000 ;
    LAYER metal4 ;
    RECT 0 0 124.450 238.000 ;
    LAYER OVERLAP ;
    RECT 0 0 124.450 238.000 ;
  END
END fakeram_128x256_1rw

END LIBRARY
